VERSION 5.8 ;
BUSBITCHARS "[]" ;
DIVIDERCHAR "/" ;
UNITS
    DATABASE MICRONS 1000 ;
END UNITS

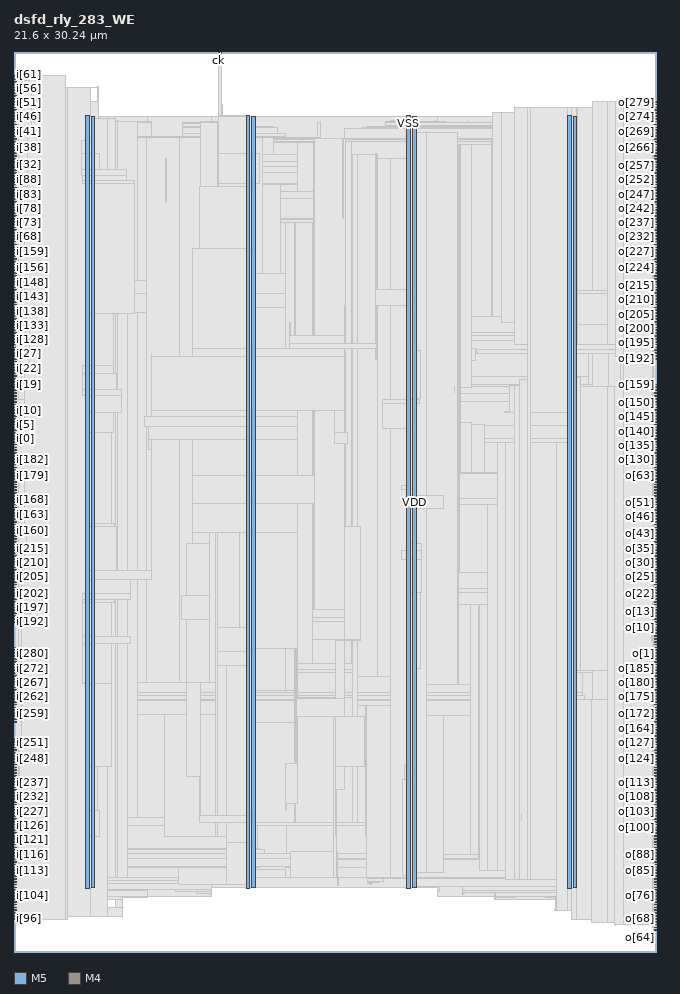
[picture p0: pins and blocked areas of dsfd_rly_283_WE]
MACRO dsfd_rly_283_WE
  FOREIGN dsfd_rly_283_WE 0 0 ;
  CLASS BLOCK ;
  SIZE 21.6 BY 30.24 ;
  PIN ck
    DIRECTION INPUT ;
    USE SIGNAL ;
    PORT
      LAYER M5 ;
        RECT  6.864 30.156 6.888 30.24 ;
    END
  END ck
  PIN i[0]
    DIRECTION INPUT ;
    USE SIGNAL ;
    PORT
      LAYER M4 ;
        RECT  0 17.232 0.084 17.256 ;
    END
  END i[0]
  PIN i[100]
    DIRECTION INPUT ;
    USE SIGNAL ;
    PORT
      LAYER M4 ;
        RECT  0 1.488 0.084 1.512 ;
    END
  END i[100]
  PIN i[101]
    DIRECTION INPUT ;
    USE SIGNAL ;
    PORT
      LAYER M4 ;
        RECT  0 1.584 0.084 1.608 ;
    END
  END i[101]
  PIN i[102]
    DIRECTION INPUT ;
    USE SIGNAL ;
    PORT
      LAYER M4 ;
        RECT  0 1.68 0.084 1.704 ;
    END
  END i[102]
  PIN i[103]
    DIRECTION INPUT ;
    USE SIGNAL ;
    PORT
      LAYER M4 ;
        RECT  0 1.776 0.084 1.8 ;
    END
  END i[103]
  PIN i[104]
    DIRECTION INPUT ;
    USE SIGNAL ;
    PORT
      LAYER M4 ;
        RECT  0 1.872 0.084 1.896 ;
    END
  END i[104]
  PIN i[105]
    DIRECTION INPUT ;
    USE SIGNAL ;
    PORT
      LAYER M4 ;
        RECT  0 1.968 0.084 1.992 ;
    END
  END i[105]
  PIN i[106]
    DIRECTION INPUT ;
    USE SIGNAL ;
    PORT
      LAYER M4 ;
        RECT  0 2.064 0.084 2.088 ;
    END
  END i[106]
  PIN i[107]
    DIRECTION INPUT ;
    USE SIGNAL ;
    PORT
      LAYER M4 ;
        RECT  0 2.16 0.084 2.184 ;
    END
  END i[107]
  PIN i[108]
    DIRECTION INPUT ;
    USE SIGNAL ;
    PORT
      LAYER M4 ;
        RECT  0 2.256 0.084 2.28 ;
    END
  END i[108]
  PIN i[109]
    DIRECTION INPUT ;
    USE SIGNAL ;
    PORT
      LAYER M4 ;
        RECT  0 2.352 0.084 2.376 ;
    END
  END i[109]
  PIN i[10]
    DIRECTION INPUT ;
    USE SIGNAL ;
    PORT
      LAYER M4 ;
        RECT  0 18.192 0.084 18.216 ;
    END
  END i[10]
  PIN i[110]
    DIRECTION INPUT ;
    USE SIGNAL ;
    PORT
      LAYER M4 ;
        RECT  0 2.448 0.084 2.472 ;
    END
  END i[110]
  PIN i[111]
    DIRECTION INPUT ;
    USE SIGNAL ;
    PORT
      LAYER M4 ;
        RECT  0 2.544 0.084 2.568 ;
    END
  END i[111]
  PIN i[112]
    DIRECTION INPUT ;
    USE SIGNAL ;
    PORT
      LAYER M4 ;
        RECT  0 2.64 0.084 2.664 ;
    END
  END i[112]
  PIN i[113]
    DIRECTION INPUT ;
    USE SIGNAL ;
    PORT
      LAYER M4 ;
        RECT  0 2.736 0.084 2.76 ;
    END
  END i[113]
  PIN i[114]
    DIRECTION INPUT ;
    USE SIGNAL ;
    PORT
      LAYER M4 ;
        RECT  0 2.832 0.084 2.856 ;
    END
  END i[114]
  PIN i[115]
    DIRECTION INPUT ;
    USE SIGNAL ;
    PORT
      LAYER M4 ;
        RECT  0 2.928 0.084 2.952 ;
    END
  END i[115]
  PIN i[116]
    DIRECTION INPUT ;
    USE SIGNAL ;
    PORT
      LAYER M4 ;
        RECT  0 3.024 0.084 3.048 ;
    END
  END i[116]
  PIN i[117]
    DIRECTION INPUT ;
    USE SIGNAL ;
    PORT
      LAYER M4 ;
        RECT  0 3.12 0.084 3.144 ;
    END
  END i[117]
  PIN i[118]
    DIRECTION INPUT ;
    USE SIGNAL ;
    PORT
      LAYER M4 ;
        RECT  0 3.216 0.084 3.24 ;
    END
  END i[118]
  PIN i[119]
    DIRECTION INPUT ;
    USE SIGNAL ;
    PORT
      LAYER M4 ;
        RECT  0 3.312 0.084 3.336 ;
    END
  END i[119]
  PIN i[11]
    DIRECTION INPUT ;
    USE SIGNAL ;
    PORT
      LAYER M4 ;
        RECT  0 18.288 0.084 18.312 ;
    END
  END i[11]
  PIN i[120]
    DIRECTION INPUT ;
    USE SIGNAL ;
    PORT
      LAYER M4 ;
        RECT  0 3.408 0.084 3.432 ;
    END
  END i[120]
  PIN i[121]
    DIRECTION INPUT ;
    USE SIGNAL ;
    PORT
      LAYER M4 ;
        RECT  0 3.504 0.084 3.528 ;
    END
  END i[121]
  PIN i[122]
    DIRECTION INPUT ;
    USE SIGNAL ;
    PORT
      LAYER M4 ;
        RECT  0 3.6 0.084 3.624 ;
    END
  END i[122]
  PIN i[123]
    DIRECTION INPUT ;
    USE SIGNAL ;
    PORT
      LAYER M4 ;
        RECT  0 3.696 0.084 3.72 ;
    END
  END i[123]
  PIN i[124]
    DIRECTION INPUT ;
    USE SIGNAL ;
    PORT
      LAYER M4 ;
        RECT  0 3.792 0.084 3.816 ;
    END
  END i[124]
  PIN i[125]
    DIRECTION INPUT ;
    USE SIGNAL ;
    PORT
      LAYER M4 ;
        RECT  0 3.888 0.084 3.912 ;
    END
  END i[125]
  PIN i[126]
    DIRECTION INPUT ;
    USE SIGNAL ;
    PORT
      LAYER M4 ;
        RECT  0 3.984 0.084 4.008 ;
    END
  END i[126]
  PIN i[127]
    DIRECTION INPUT ;
    USE SIGNAL ;
    PORT
      LAYER M4 ;
        RECT  0 4.08 0.084 4.104 ;
    END
  END i[127]
  PIN i[128]
    DIRECTION INPUT ;
    USE SIGNAL ;
    PORT
      LAYER M4 ;
        RECT  0 20.304 0.084 20.328 ;
    END
  END i[128]
  PIN i[129]
    DIRECTION INPUT ;
    USE SIGNAL ;
    PORT
      LAYER M4 ;
        RECT  0 20.4 0.084 20.424 ;
    END
  END i[129]
  PIN i[12]
    DIRECTION INPUT ;
    USE SIGNAL ;
    PORT
      LAYER M4 ;
        RECT  0 18.384 0.084 18.408 ;
    END
  END i[12]
  PIN i[130]
    DIRECTION INPUT ;
    USE SIGNAL ;
    PORT
      LAYER M4 ;
        RECT  0 20.496 0.084 20.52 ;
    END
  END i[130]
  PIN i[131]
    DIRECTION INPUT ;
    USE SIGNAL ;
    PORT
      LAYER M4 ;
        RECT  0 20.592 0.084 20.616 ;
    END
  END i[131]
  PIN i[132]
    DIRECTION INPUT ;
    USE SIGNAL ;
    PORT
      LAYER M4 ;
        RECT  0 20.688 0.084 20.712 ;
    END
  END i[132]
  PIN i[133]
    DIRECTION INPUT ;
    USE SIGNAL ;
    PORT
      LAYER M4 ;
        RECT  0 20.784 0.084 20.808 ;
    END
  END i[133]
  PIN i[134]
    DIRECTION INPUT ;
    USE SIGNAL ;
    PORT
      LAYER M4 ;
        RECT  0 20.88 0.084 20.904 ;
    END
  END i[134]
  PIN i[135]
    DIRECTION INPUT ;
    USE SIGNAL ;
    PORT
      LAYER M4 ;
        RECT  0 20.976 0.084 21 ;
    END
  END i[135]
  PIN i[136]
    DIRECTION INPUT ;
    USE SIGNAL ;
    PORT
      LAYER M4 ;
        RECT  0 21.072 0.084 21.096 ;
    END
  END i[136]
  PIN i[137]
    DIRECTION INPUT ;
    USE SIGNAL ;
    PORT
      LAYER M4 ;
        RECT  0 21.168 0.084 21.192 ;
    END
  END i[137]
  PIN i[138]
    DIRECTION INPUT ;
    USE SIGNAL ;
    PORT
      LAYER M4 ;
        RECT  0 21.264 0.084 21.288 ;
    END
  END i[138]
  PIN i[139]
    DIRECTION INPUT ;
    USE SIGNAL ;
    PORT
      LAYER M4 ;
        RECT  0 21.36 0.084 21.384 ;
    END
  END i[139]
  PIN i[13]
    DIRECTION INPUT ;
    USE SIGNAL ;
    PORT
      LAYER M4 ;
        RECT  0 18.48 0.084 18.504 ;
    END
  END i[13]
  PIN i[140]
    DIRECTION INPUT ;
    USE SIGNAL ;
    PORT
      LAYER M4 ;
        RECT  0 21.456 0.084 21.48 ;
    END
  END i[140]
  PIN i[141]
    DIRECTION INPUT ;
    USE SIGNAL ;
    PORT
      LAYER M4 ;
        RECT  0 21.552 0.084 21.576 ;
    END
  END i[141]
  PIN i[142]
    DIRECTION INPUT ;
    USE SIGNAL ;
    PORT
      LAYER M4 ;
        RECT  0 21.648 0.084 21.672 ;
    END
  END i[142]
  PIN i[143]
    DIRECTION INPUT ;
    USE SIGNAL ;
    PORT
      LAYER M4 ;
        RECT  0 21.744 0.084 21.768 ;
    END
  END i[143]
  PIN i[144]
    DIRECTION INPUT ;
    USE SIGNAL ;
    PORT
      LAYER M4 ;
        RECT  0 21.84 0.084 21.864 ;
    END
  END i[144]
  PIN i[145]
    DIRECTION INPUT ;
    USE SIGNAL ;
    PORT
      LAYER M4 ;
        RECT  0 21.936 0.084 21.96 ;
    END
  END i[145]
  PIN i[146]
    DIRECTION INPUT ;
    USE SIGNAL ;
    PORT
      LAYER M4 ;
        RECT  0 22.032 0.084 22.056 ;
    END
  END i[146]
  PIN i[147]
    DIRECTION INPUT ;
    USE SIGNAL ;
    PORT
      LAYER M4 ;
        RECT  0 22.128 0.084 22.152 ;
    END
  END i[147]
  PIN i[148]
    DIRECTION INPUT ;
    USE SIGNAL ;
    PORT
      LAYER M4 ;
        RECT  0 22.224 0.084 22.248 ;
    END
  END i[148]
  PIN i[149]
    DIRECTION INPUT ;
    USE SIGNAL ;
    PORT
      LAYER M4 ;
        RECT  0 22.32 0.084 22.344 ;
    END
  END i[149]
  PIN i[14]
    DIRECTION INPUT ;
    USE SIGNAL ;
    PORT
      LAYER M4 ;
        RECT  0 18.576 0.084 18.6 ;
    END
  END i[14]
  PIN i[150]
    DIRECTION INPUT ;
    USE SIGNAL ;
    PORT
      LAYER M4 ;
        RECT  0 22.416 0.084 22.44 ;
    END
  END i[150]
  PIN i[151]
    DIRECTION INPUT ;
    USE SIGNAL ;
    PORT
      LAYER M4 ;
        RECT  0 22.512 0.084 22.536 ;
    END
  END i[151]
  PIN i[152]
    DIRECTION INPUT ;
    USE SIGNAL ;
    PORT
      LAYER M4 ;
        RECT  0 22.608 0.084 22.632 ;
    END
  END i[152]
  PIN i[153]
    DIRECTION INPUT ;
    USE SIGNAL ;
    PORT
      LAYER M4 ;
        RECT  0 22.704 0.084 22.728 ;
    END
  END i[153]
  PIN i[154]
    DIRECTION INPUT ;
    USE SIGNAL ;
    PORT
      LAYER M4 ;
        RECT  0 22.8 0.084 22.824 ;
    END
  END i[154]
  PIN i[155]
    DIRECTION INPUT ;
    USE SIGNAL ;
    PORT
      LAYER M4 ;
        RECT  0 22.896 0.084 22.92 ;
    END
  END i[155]
  PIN i[156]
    DIRECTION INPUT ;
    USE SIGNAL ;
    PORT
      LAYER M4 ;
        RECT  0 22.992 0.084 23.016 ;
    END
  END i[156]
  PIN i[157]
    DIRECTION INPUT ;
    USE SIGNAL ;
    PORT
      LAYER M4 ;
        RECT  0 23.088 0.084 23.112 ;
    END
  END i[157]
  PIN i[158]
    DIRECTION INPUT ;
    USE SIGNAL ;
    PORT
      LAYER M4 ;
        RECT  0 23.184 0.084 23.208 ;
    END
  END i[158]
  PIN i[159]
    DIRECTION INPUT ;
    USE SIGNAL ;
    PORT
      LAYER M4 ;
        RECT  0 23.28 0.084 23.304 ;
    END
  END i[159]
  PIN i[15]
    DIRECTION INPUT ;
    USE SIGNAL ;
    PORT
      LAYER M4 ;
        RECT  0 18.672 0.084 18.696 ;
    END
  END i[15]
  PIN i[160]
    DIRECTION INPUT ;
    USE SIGNAL ;
    PORT
      LAYER M4 ;
        RECT  0 14.16 0.084 14.184 ;
    END
  END i[160]
  PIN i[161]
    DIRECTION INPUT ;
    USE SIGNAL ;
    PORT
      LAYER M4 ;
        RECT  0 14.256 0.084 14.28 ;
    END
  END i[161]
  PIN i[162]
    DIRECTION INPUT ;
    USE SIGNAL ;
    PORT
      LAYER M4 ;
        RECT  0 14.352 0.084 14.376 ;
    END
  END i[162]
  PIN i[163]
    DIRECTION INPUT ;
    USE SIGNAL ;
    PORT
      LAYER M4 ;
        RECT  0 14.448 0.084 14.472 ;
    END
  END i[163]
  PIN i[164]
    DIRECTION INPUT ;
    USE SIGNAL ;
    PORT
      LAYER M4 ;
        RECT  0 14.544 0.084 14.568 ;
    END
  END i[164]
  PIN i[165]
    DIRECTION INPUT ;
    USE SIGNAL ;
    PORT
      LAYER M4 ;
        RECT  0 14.64 0.084 14.664 ;
    END
  END i[165]
  PIN i[166]
    DIRECTION INPUT ;
    USE SIGNAL ;
    PORT
      LAYER M4 ;
        RECT  0 14.736 0.084 14.76 ;
    END
  END i[166]
  PIN i[167]
    DIRECTION INPUT ;
    USE SIGNAL ;
    PORT
      LAYER M4 ;
        RECT  0 14.832 0.084 14.856 ;
    END
  END i[167]
  PIN i[168]
    DIRECTION INPUT ;
    USE SIGNAL ;
    PORT
      LAYER M4 ;
        RECT  0 14.928 0.084 14.952 ;
    END
  END i[168]
  PIN i[169]
    DIRECTION INPUT ;
    USE SIGNAL ;
    PORT
      LAYER M4 ;
        RECT  0 15.024 0.084 15.048 ;
    END
  END i[169]
  PIN i[16]
    DIRECTION INPUT ;
    USE SIGNAL ;
    PORT
      LAYER M4 ;
        RECT  0 18.768 0.084 18.792 ;
    END
  END i[16]
  PIN i[170]
    DIRECTION INPUT ;
    USE SIGNAL ;
    PORT
      LAYER M4 ;
        RECT  0 15.12 0.084 15.144 ;
    END
  END i[170]
  PIN i[171]
    DIRECTION INPUT ;
    USE SIGNAL ;
    PORT
      LAYER M4 ;
        RECT  0 15.216 0.084 15.24 ;
    END
  END i[171]
  PIN i[172]
    DIRECTION INPUT ;
    USE SIGNAL ;
    PORT
      LAYER M4 ;
        RECT  0 15.312 0.084 15.336 ;
    END
  END i[172]
  PIN i[173]
    DIRECTION INPUT ;
    USE SIGNAL ;
    PORT
      LAYER M4 ;
        RECT  0 15.408 0.084 15.432 ;
    END
  END i[173]
  PIN i[174]
    DIRECTION INPUT ;
    USE SIGNAL ;
    PORT
      LAYER M4 ;
        RECT  0 15.504 0.084 15.528 ;
    END
  END i[174]
  PIN i[175]
    DIRECTION INPUT ;
    USE SIGNAL ;
    PORT
      LAYER M4 ;
        RECT  0 15.6 0.084 15.624 ;
    END
  END i[175]
  PIN i[176]
    DIRECTION INPUT ;
    USE SIGNAL ;
    PORT
      LAYER M4 ;
        RECT  0 15.696 0.084 15.72 ;
    END
  END i[176]
  PIN i[177]
    DIRECTION INPUT ;
    USE SIGNAL ;
    PORT
      LAYER M4 ;
        RECT  0 15.792 0.084 15.816 ;
    END
  END i[177]
  PIN i[178]
    DIRECTION INPUT ;
    USE SIGNAL ;
    PORT
      LAYER M4 ;
        RECT  0 15.888 0.084 15.912 ;
    END
  END i[178]
  PIN i[179]
    DIRECTION INPUT ;
    USE SIGNAL ;
    PORT
      LAYER M4 ;
        RECT  0 15.984 0.084 16.008 ;
    END
  END i[179]
  PIN i[17]
    DIRECTION INPUT ;
    USE SIGNAL ;
    PORT
      LAYER M4 ;
        RECT  0 18.864 0.084 18.888 ;
    END
  END i[17]
  PIN i[180]
    DIRECTION INPUT ;
    USE SIGNAL ;
    PORT
      LAYER M4 ;
        RECT  0 16.08 0.084 16.104 ;
    END
  END i[180]
  PIN i[181]
    DIRECTION INPUT ;
    USE SIGNAL ;
    PORT
      LAYER M4 ;
        RECT  0 16.176 0.084 16.2 ;
    END
  END i[181]
  PIN i[182]
    DIRECTION INPUT ;
    USE SIGNAL ;
    PORT
      LAYER M4 ;
        RECT  0 16.272 0.084 16.296 ;
    END
  END i[182]
  PIN i[183]
    DIRECTION INPUT ;
    USE SIGNAL ;
    PORT
      LAYER M4 ;
        RECT  0 16.368 0.084 16.392 ;
    END
  END i[183]
  PIN i[184]
    DIRECTION INPUT ;
    USE SIGNAL ;
    PORT
      LAYER M4 ;
        RECT  0 16.464 0.084 16.488 ;
    END
  END i[184]
  PIN i[185]
    DIRECTION INPUT ;
    USE SIGNAL ;
    PORT
      LAYER M4 ;
        RECT  0 16.56 0.084 16.584 ;
    END
  END i[185]
  PIN i[186]
    DIRECTION INPUT ;
    USE SIGNAL ;
    PORT
      LAYER M4 ;
        RECT  0 16.656 0.084 16.68 ;
    END
  END i[186]
  PIN i[187]
    DIRECTION INPUT ;
    USE SIGNAL ;
    PORT
      LAYER M4 ;
        RECT  0 16.752 0.084 16.776 ;
    END
  END i[187]
  PIN i[188]
    DIRECTION INPUT ;
    USE SIGNAL ;
    PORT
      LAYER M4 ;
        RECT  0 16.848 0.084 16.872 ;
    END
  END i[188]
  PIN i[189]
    DIRECTION INPUT ;
    USE SIGNAL ;
    PORT
      LAYER M4 ;
        RECT  0 16.944 0.084 16.968 ;
    END
  END i[189]
  PIN i[18]
    DIRECTION INPUT ;
    USE SIGNAL ;
    PORT
      LAYER M4 ;
        RECT  0 18.96 0.084 18.984 ;
    END
  END i[18]
  PIN i[190]
    DIRECTION INPUT ;
    USE SIGNAL ;
    PORT
      LAYER M4 ;
        RECT  0 17.04 0.084 17.064 ;
    END
  END i[190]
  PIN i[191]
    DIRECTION INPUT ;
    USE SIGNAL ;
    PORT
      LAYER M4 ;
        RECT  0 17.136 0.084 17.16 ;
    END
  END i[191]
  PIN i[192]
    DIRECTION INPUT ;
    USE SIGNAL ;
    PORT
      LAYER M4 ;
        RECT  0 11.088 0.084 11.112 ;
    END
  END i[192]
  PIN i[193]
    DIRECTION INPUT ;
    USE SIGNAL ;
    PORT
      LAYER M4 ;
        RECT  0 11.184 0.084 11.208 ;
    END
  END i[193]
  PIN i[194]
    DIRECTION INPUT ;
    USE SIGNAL ;
    PORT
      LAYER M4 ;
        RECT  0 11.28 0.084 11.304 ;
    END
  END i[194]
  PIN i[195]
    DIRECTION INPUT ;
    USE SIGNAL ;
    PORT
      LAYER M4 ;
        RECT  0 11.376 0.084 11.4 ;
    END
  END i[195]
  PIN i[196]
    DIRECTION INPUT ;
    USE SIGNAL ;
    PORT
      LAYER M4 ;
        RECT  0 11.472 0.084 11.496 ;
    END
  END i[196]
  PIN i[197]
    DIRECTION INPUT ;
    USE SIGNAL ;
    PORT
      LAYER M4 ;
        RECT  0 11.568 0.084 11.592 ;
    END
  END i[197]
  PIN i[198]
    DIRECTION INPUT ;
    USE SIGNAL ;
    PORT
      LAYER M4 ;
        RECT  0 11.664 0.084 11.688 ;
    END
  END i[198]
  PIN i[199]
    DIRECTION INPUT ;
    USE SIGNAL ;
    PORT
      LAYER M4 ;
        RECT  0 11.76 0.084 11.784 ;
    END
  END i[199]
  PIN i[19]
    DIRECTION INPUT ;
    USE SIGNAL ;
    PORT
      LAYER M4 ;
        RECT  0 19.056 0.084 19.08 ;
    END
  END i[19]
  PIN i[1]
    DIRECTION INPUT ;
    USE SIGNAL ;
    PORT
      LAYER M4 ;
        RECT  0 17.328 0.084 17.352 ;
    END
  END i[1]
  PIN i[200]
    DIRECTION INPUT ;
    USE SIGNAL ;
    PORT
      LAYER M4 ;
        RECT  0 11.856 0.084 11.88 ;
    END
  END i[200]
  PIN i[201]
    DIRECTION INPUT ;
    USE SIGNAL ;
    PORT
      LAYER M4 ;
        RECT  0 11.952 0.084 11.976 ;
    END
  END i[201]
  PIN i[202]
    DIRECTION INPUT ;
    USE SIGNAL ;
    PORT
      LAYER M4 ;
        RECT  0 12.048 0.084 12.072 ;
    END
  END i[202]
  PIN i[203]
    DIRECTION INPUT ;
    USE SIGNAL ;
    PORT
      LAYER M4 ;
        RECT  0 12.144 0.084 12.168 ;
    END
  END i[203]
  PIN i[204]
    DIRECTION INPUT ;
    USE SIGNAL ;
    PORT
      LAYER M4 ;
        RECT  0 12.24 0.084 12.264 ;
    END
  END i[204]
  PIN i[205]
    DIRECTION INPUT ;
    USE SIGNAL ;
    PORT
      LAYER M4 ;
        RECT  0 12.336 0.084 12.36 ;
    END
  END i[205]
  PIN i[206]
    DIRECTION INPUT ;
    USE SIGNAL ;
    PORT
      LAYER M4 ;
        RECT  0 12.432 0.084 12.456 ;
    END
  END i[206]
  PIN i[207]
    DIRECTION INPUT ;
    USE SIGNAL ;
    PORT
      LAYER M4 ;
        RECT  0 12.528 0.084 12.552 ;
    END
  END i[207]
  PIN i[208]
    DIRECTION INPUT ;
    USE SIGNAL ;
    PORT
      LAYER M4 ;
        RECT  0 12.624 0.084 12.648 ;
    END
  END i[208]
  PIN i[209]
    DIRECTION INPUT ;
    USE SIGNAL ;
    PORT
      LAYER M4 ;
        RECT  0 12.72 0.084 12.744 ;
    END
  END i[209]
  PIN i[20]
    DIRECTION INPUT ;
    USE SIGNAL ;
    PORT
      LAYER M4 ;
        RECT  0 19.152 0.084 19.176 ;
    END
  END i[20]
  PIN i[210]
    DIRECTION INPUT ;
    USE SIGNAL ;
    PORT
      LAYER M4 ;
        RECT  0 12.816 0.084 12.84 ;
    END
  END i[210]
  PIN i[211]
    DIRECTION INPUT ;
    USE SIGNAL ;
    PORT
      LAYER M4 ;
        RECT  0 12.912 0.084 12.936 ;
    END
  END i[211]
  PIN i[212]
    DIRECTION INPUT ;
    USE SIGNAL ;
    PORT
      LAYER M4 ;
        RECT  0 13.008 0.084 13.032 ;
    END
  END i[212]
  PIN i[213]
    DIRECTION INPUT ;
    USE SIGNAL ;
    PORT
      LAYER M4 ;
        RECT  0 13.104 0.084 13.128 ;
    END
  END i[213]
  PIN i[214]
    DIRECTION INPUT ;
    USE SIGNAL ;
    PORT
      LAYER M4 ;
        RECT  0 13.2 0.084 13.224 ;
    END
  END i[214]
  PIN i[215]
    DIRECTION INPUT ;
    USE SIGNAL ;
    PORT
      LAYER M4 ;
        RECT  0 13.296 0.084 13.32 ;
    END
  END i[215]
  PIN i[216]
    DIRECTION INPUT ;
    USE SIGNAL ;
    PORT
      LAYER M4 ;
        RECT  0 13.392 0.084 13.416 ;
    END
  END i[216]
  PIN i[217]
    DIRECTION INPUT ;
    USE SIGNAL ;
    PORT
      LAYER M4 ;
        RECT  0 13.488 0.084 13.512 ;
    END
  END i[217]
  PIN i[218]
    DIRECTION INPUT ;
    USE SIGNAL ;
    PORT
      LAYER M4 ;
        RECT  0 13.584 0.084 13.608 ;
    END
  END i[218]
  PIN i[219]
    DIRECTION INPUT ;
    USE SIGNAL ;
    PORT
      LAYER M4 ;
        RECT  0 13.68 0.084 13.704 ;
    END
  END i[219]
  PIN i[21]
    DIRECTION INPUT ;
    USE SIGNAL ;
    PORT
      LAYER M4 ;
        RECT  0 19.248 0.084 19.272 ;
    END
  END i[21]
  PIN i[220]
    DIRECTION INPUT ;
    USE SIGNAL ;
    PORT
      LAYER M4 ;
        RECT  0 13.776 0.084 13.8 ;
    END
  END i[220]
  PIN i[221]
    DIRECTION INPUT ;
    USE SIGNAL ;
    PORT
      LAYER M4 ;
        RECT  0 13.872 0.084 13.896 ;
    END
  END i[221]
  PIN i[222]
    DIRECTION INPUT ;
    USE SIGNAL ;
    PORT
      LAYER M4 ;
        RECT  0 13.968 0.084 13.992 ;
    END
  END i[222]
  PIN i[223]
    DIRECTION INPUT ;
    USE SIGNAL ;
    PORT
      LAYER M4 ;
        RECT  0 14.064 0.084 14.088 ;
    END
  END i[223]
  PIN i[224]
    DIRECTION INPUT ;
    USE SIGNAL ;
    PORT
      LAYER M4 ;
        RECT  0 4.176 0.084 4.2 ;
    END
  END i[224]
  PIN i[225]
    DIRECTION INPUT ;
    USE SIGNAL ;
    PORT
      LAYER M4 ;
        RECT  0 4.272 0.084 4.296 ;
    END
  END i[225]
  PIN i[226]
    DIRECTION INPUT ;
    USE SIGNAL ;
    PORT
      LAYER M4 ;
        RECT  0 4.368 0.084 4.392 ;
    END
  END i[226]
  PIN i[227]
    DIRECTION INPUT ;
    USE SIGNAL ;
    PORT
      LAYER M4 ;
        RECT  0 4.464 0.084 4.488 ;
    END
  END i[227]
  PIN i[228]
    DIRECTION INPUT ;
    USE SIGNAL ;
    PORT
      LAYER M4 ;
        RECT  0 4.56 0.084 4.584 ;
    END
  END i[228]
  PIN i[229]
    DIRECTION INPUT ;
    USE SIGNAL ;
    PORT
      LAYER M4 ;
        RECT  0 4.656 0.084 4.68 ;
    END
  END i[229]
  PIN i[22]
    DIRECTION INPUT ;
    USE SIGNAL ;
    PORT
      LAYER M4 ;
        RECT  0 19.344 0.084 19.368 ;
    END
  END i[22]
  PIN i[230]
    DIRECTION INPUT ;
    USE SIGNAL ;
    PORT
      LAYER M4 ;
        RECT  0 4.752 0.084 4.776 ;
    END
  END i[230]
  PIN i[231]
    DIRECTION INPUT ;
    USE SIGNAL ;
    PORT
      LAYER M4 ;
        RECT  0 4.848 0.084 4.872 ;
    END
  END i[231]
  PIN i[232]
    DIRECTION INPUT ;
    USE SIGNAL ;
    PORT
      LAYER M4 ;
        RECT  0 4.944 0.084 4.968 ;
    END
  END i[232]
  PIN i[233]
    DIRECTION INPUT ;
    USE SIGNAL ;
    PORT
      LAYER M4 ;
        RECT  0 5.04 0.084 5.064 ;
    END
  END i[233]
  PIN i[234]
    DIRECTION INPUT ;
    USE SIGNAL ;
    PORT
      LAYER M4 ;
        RECT  0 5.136 0.084 5.16 ;
    END
  END i[234]
  PIN i[235]
    DIRECTION INPUT ;
    USE SIGNAL ;
    PORT
      LAYER M4 ;
        RECT  0 5.232 0.084 5.256 ;
    END
  END i[235]
  PIN i[236]
    DIRECTION INPUT ;
    USE SIGNAL ;
    PORT
      LAYER M4 ;
        RECT  0 5.328 0.084 5.352 ;
    END
  END i[236]
  PIN i[237]
    DIRECTION INPUT ;
    USE SIGNAL ;
    PORT
      LAYER M4 ;
        RECT  0 5.424 0.084 5.448 ;
    END
  END i[237]
  PIN i[238]
    DIRECTION INPUT ;
    USE SIGNAL ;
    PORT
      LAYER M4 ;
        RECT  0 5.52 0.084 5.544 ;
    END
  END i[238]
  PIN i[239]
    DIRECTION INPUT ;
    USE SIGNAL ;
    PORT
      LAYER M4 ;
        RECT  0 5.616 0.084 5.64 ;
    END
  END i[239]
  PIN i[23]
    DIRECTION INPUT ;
    USE SIGNAL ;
    PORT
      LAYER M4 ;
        RECT  0 19.44 0.084 19.464 ;
    END
  END i[23]
  PIN i[240]
    DIRECTION INPUT ;
    USE SIGNAL ;
    PORT
      LAYER M4 ;
        RECT  0 5.712 0.084 5.736 ;
    END
  END i[240]
  PIN i[241]
    DIRECTION INPUT ;
    USE SIGNAL ;
    PORT
      LAYER M4 ;
        RECT  0 5.808 0.084 5.832 ;
    END
  END i[241]
  PIN i[242]
    DIRECTION INPUT ;
    USE SIGNAL ;
    PORT
      LAYER M4 ;
        RECT  0 5.904 0.084 5.928 ;
    END
  END i[242]
  PIN i[243]
    DIRECTION INPUT ;
    USE SIGNAL ;
    PORT
      LAYER M4 ;
        RECT  0 6 0.084 6.024 ;
    END
  END i[243]
  PIN i[244]
    DIRECTION INPUT ;
    USE SIGNAL ;
    PORT
      LAYER M4 ;
        RECT  0 6.096 0.084 6.12 ;
    END
  END i[244]
  PIN i[245]
    DIRECTION INPUT ;
    USE SIGNAL ;
    PORT
      LAYER M4 ;
        RECT  0 6.192 0.084 6.216 ;
    END
  END i[245]
  PIN i[246]
    DIRECTION INPUT ;
    USE SIGNAL ;
    PORT
      LAYER M4 ;
        RECT  0 6.288 0.084 6.312 ;
    END
  END i[246]
  PIN i[247]
    DIRECTION INPUT ;
    USE SIGNAL ;
    PORT
      LAYER M4 ;
        RECT  0 6.384 0.084 6.408 ;
    END
  END i[247]
  PIN i[248]
    DIRECTION INPUT ;
    USE SIGNAL ;
    PORT
      LAYER M4 ;
        RECT  0 6.48 0.084 6.504 ;
    END
  END i[248]
  PIN i[249]
    DIRECTION INPUT ;
    USE SIGNAL ;
    PORT
      LAYER M4 ;
        RECT  0 6.576 0.084 6.6 ;
    END
  END i[249]
  PIN i[24]
    DIRECTION INPUT ;
    USE SIGNAL ;
    PORT
      LAYER M4 ;
        RECT  0 19.536 0.084 19.56 ;
    END
  END i[24]
  PIN i[250]
    DIRECTION INPUT ;
    USE SIGNAL ;
    PORT
      LAYER M4 ;
        RECT  0 6.672 0.084 6.696 ;
    END
  END i[250]
  PIN i[251]
    DIRECTION INPUT ;
    USE SIGNAL ;
    PORT
      LAYER M4 ;
        RECT  0 6.768 0.084 6.792 ;
    END
  END i[251]
  PIN i[252]
    DIRECTION INPUT ;
    USE SIGNAL ;
    PORT
      LAYER M4 ;
        RECT  0 6.864 0.084 6.888 ;
    END
  END i[252]
  PIN i[253]
    DIRECTION INPUT ;
    USE SIGNAL ;
    PORT
      LAYER M4 ;
        RECT  0 6.96 0.084 6.984 ;
    END
  END i[253]
  PIN i[254]
    DIRECTION INPUT ;
    USE SIGNAL ;
    PORT
      LAYER M4 ;
        RECT  0 7.056 0.084 7.08 ;
    END
  END i[254]
  PIN i[255]
    DIRECTION INPUT ;
    USE SIGNAL ;
    PORT
      LAYER M4 ;
        RECT  0 7.152 0.084 7.176 ;
    END
  END i[255]
  PIN i[256]
    DIRECTION INPUT ;
    USE SIGNAL ;
    PORT
      LAYER M4 ;
        RECT  0 7.728 0.084 7.752 ;
    END
  END i[256]
  PIN i[257]
    DIRECTION INPUT ;
    USE SIGNAL ;
    PORT
      LAYER M4 ;
        RECT  0 7.824 0.084 7.848 ;
    END
  END i[257]
  PIN i[258]
    DIRECTION INPUT ;
    USE SIGNAL ;
    PORT
      LAYER M4 ;
        RECT  0 7.92 0.084 7.944 ;
    END
  END i[258]
  PIN i[259]
    DIRECTION INPUT ;
    USE SIGNAL ;
    PORT
      LAYER M4 ;
        RECT  0 8.016 0.084 8.04 ;
    END
  END i[259]
  PIN i[25]
    DIRECTION INPUT ;
    USE SIGNAL ;
    PORT
      LAYER M4 ;
        RECT  0 19.632 0.084 19.656 ;
    END
  END i[25]
  PIN i[260]
    DIRECTION INPUT ;
    USE SIGNAL ;
    PORT
      LAYER M4 ;
        RECT  0 8.112 0.084 8.136 ;
    END
  END i[260]
  PIN i[261]
    DIRECTION INPUT ;
    USE SIGNAL ;
    PORT
      LAYER M4 ;
        RECT  0 8.208 0.084 8.232 ;
    END
  END i[261]
  PIN i[262]
    DIRECTION INPUT ;
    USE SIGNAL ;
    PORT
      LAYER M4 ;
        RECT  0 8.304 0.084 8.328 ;
    END
  END i[262]
  PIN i[263]
    DIRECTION INPUT ;
    USE SIGNAL ;
    PORT
      LAYER M4 ;
        RECT  0 8.4 0.084 8.424 ;
    END
  END i[263]
  PIN i[264]
    DIRECTION INPUT ;
    USE SIGNAL ;
    PORT
      LAYER M4 ;
        RECT  0 8.496 0.084 8.52 ;
    END
  END i[264]
  PIN i[265]
    DIRECTION INPUT ;
    USE SIGNAL ;
    PORT
      LAYER M4 ;
        RECT  0 8.592 0.084 8.616 ;
    END
  END i[265]
  PIN i[266]
    DIRECTION INPUT ;
    USE SIGNAL ;
    PORT
      LAYER M4 ;
        RECT  0 8.688 0.084 8.712 ;
    END
  END i[266]
  PIN i[267]
    DIRECTION INPUT ;
    USE SIGNAL ;
    PORT
      LAYER M4 ;
        RECT  0 8.784 0.084 8.808 ;
    END
  END i[267]
  PIN i[268]
    DIRECTION INPUT ;
    USE SIGNAL ;
    PORT
      LAYER M4 ;
        RECT  0 8.88 0.084 8.904 ;
    END
  END i[268]
  PIN i[269]
    DIRECTION INPUT ;
    USE SIGNAL ;
    PORT
      LAYER M4 ;
        RECT  0 8.976 0.084 9 ;
    END
  END i[269]
  PIN i[26]
    DIRECTION INPUT ;
    USE SIGNAL ;
    PORT
      LAYER M4 ;
        RECT  0 19.728 0.084 19.752 ;
    END
  END i[26]
  PIN i[270]
    DIRECTION INPUT ;
    USE SIGNAL ;
    PORT
      LAYER M4 ;
        RECT  0 9.072 0.084 9.096 ;
    END
  END i[270]
  PIN i[271]
    DIRECTION INPUT ;
    USE SIGNAL ;
    PORT
      LAYER M4 ;
        RECT  0 9.168 0.084 9.192 ;
    END
  END i[271]
  PIN i[272]
    DIRECTION INPUT ;
    USE SIGNAL ;
    PORT
      LAYER M4 ;
        RECT  0 9.264 0.084 9.288 ;
    END
  END i[272]
  PIN i[273]
    DIRECTION INPUT ;
    USE SIGNAL ;
    PORT
      LAYER M4 ;
        RECT  0 9.36 0.084 9.384 ;
    END
  END i[273]
  PIN i[274]
    DIRECTION INPUT ;
    USE SIGNAL ;
    PORT
      LAYER M4 ;
        RECT  0 9.456 0.084 9.48 ;
    END
  END i[274]
  PIN i[275]
    DIRECTION INPUT ;
    USE SIGNAL ;
    PORT
      LAYER M4 ;
        RECT  0 9.552 0.084 9.576 ;
    END
  END i[275]
  PIN i[276]
    DIRECTION INPUT ;
    USE SIGNAL ;
    PORT
      LAYER M4 ;
        RECT  0 9.648 0.084 9.672 ;
    END
  END i[276]
  PIN i[277]
    DIRECTION INPUT ;
    USE SIGNAL ;
    PORT
      LAYER M4 ;
        RECT  0 9.744 0.084 9.768 ;
    END
  END i[277]
  PIN i[278]
    DIRECTION INPUT ;
    USE SIGNAL ;
    PORT
      LAYER M4 ;
        RECT  0 9.84 0.084 9.864 ;
    END
  END i[278]
  PIN i[279]
    DIRECTION INPUT ;
    USE SIGNAL ;
    PORT
      LAYER M4 ;
        RECT  0 9.936 0.084 9.96 ;
    END
  END i[279]
  PIN i[27]
    DIRECTION INPUT ;
    USE SIGNAL ;
    PORT
      LAYER M4 ;
        RECT  0 19.824 0.084 19.848 ;
    END
  END i[27]
  PIN i[280]
    DIRECTION INPUT ;
    USE SIGNAL ;
    PORT
      LAYER M4 ;
        RECT  0 10.032 0.084 10.056 ;
    END
  END i[280]
  PIN i[281]
    DIRECTION INPUT ;
    USE SIGNAL ;
    PORT
      LAYER M4 ;
        RECT  0 10.128 0.084 10.152 ;
    END
  END i[281]
  PIN i[282]
    DIRECTION INPUT ;
    USE SIGNAL ;
    PORT
      LAYER M4 ;
        RECT  0 10.224 0.084 10.248 ;
    END
  END i[282]
  PIN i[28]
    DIRECTION INPUT ;
    USE SIGNAL ;
    PORT
      LAYER M4 ;
        RECT  0 19.92 0.084 19.944 ;
    END
  END i[28]
  PIN i[29]
    DIRECTION INPUT ;
    USE SIGNAL ;
    PORT
      LAYER M4 ;
        RECT  0 20.016 0.084 20.04 ;
    END
  END i[29]
  PIN i[2]
    DIRECTION INPUT ;
    USE SIGNAL ;
    PORT
      LAYER M4 ;
        RECT  0 17.424 0.084 17.448 ;
    END
  END i[2]
  PIN i[30]
    DIRECTION INPUT ;
    USE SIGNAL ;
    PORT
      LAYER M4 ;
        RECT  0 20.112 0.084 20.136 ;
    END
  END i[30]
  PIN i[31]
    DIRECTION INPUT ;
    USE SIGNAL ;
    PORT
      LAYER M4 ;
        RECT  0 20.208 0.084 20.232 ;
    END
  END i[31]
  PIN i[32]
    DIRECTION INPUT ;
    USE SIGNAL ;
    PORT
      LAYER M4 ;
        RECT  0 26.448 0.084 26.472 ;
    END
  END i[32]
  PIN i[33]
    DIRECTION INPUT ;
    USE SIGNAL ;
    PORT
      LAYER M4 ;
        RECT  0 26.544 0.084 26.568 ;
    END
  END i[33]
  PIN i[34]
    DIRECTION INPUT ;
    USE SIGNAL ;
    PORT
      LAYER M4 ;
        RECT  0 26.64 0.084 26.664 ;
    END
  END i[34]
  PIN i[35]
    DIRECTION INPUT ;
    USE SIGNAL ;
    PORT
      LAYER M4 ;
        RECT  0 26.736 0.084 26.76 ;
    END
  END i[35]
  PIN i[36]
    DIRECTION INPUT ;
    USE SIGNAL ;
    PORT
      LAYER M4 ;
        RECT  0 26.832 0.084 26.856 ;
    END
  END i[36]
  PIN i[37]
    DIRECTION INPUT ;
    USE SIGNAL ;
    PORT
      LAYER M4 ;
        RECT  0 26.928 0.084 26.952 ;
    END
  END i[37]
  PIN i[38]
    DIRECTION INPUT ;
    USE SIGNAL ;
    PORT
      LAYER M4 ;
        RECT  0 27.024 0.084 27.048 ;
    END
  END i[38]
  PIN i[39]
    DIRECTION INPUT ;
    USE SIGNAL ;
    PORT
      LAYER M4 ;
        RECT  0 27.12 0.084 27.144 ;
    END
  END i[39]
  PIN i[3]
    DIRECTION INPUT ;
    USE SIGNAL ;
    PORT
      LAYER M4 ;
        RECT  0 17.52 0.084 17.544 ;
    END
  END i[3]
  PIN i[40]
    DIRECTION INPUT ;
    USE SIGNAL ;
    PORT
      LAYER M4 ;
        RECT  0 27.216 0.084 27.24 ;
    END
  END i[40]
  PIN i[41]
    DIRECTION INPUT ;
    USE SIGNAL ;
    PORT
      LAYER M4 ;
        RECT  0 27.312 0.084 27.336 ;
    END
  END i[41]
  PIN i[42]
    DIRECTION INPUT ;
    USE SIGNAL ;
    PORT
      LAYER M4 ;
        RECT  0 27.408 0.084 27.432 ;
    END
  END i[42]
  PIN i[43]
    DIRECTION INPUT ;
    USE SIGNAL ;
    PORT
      LAYER M4 ;
        RECT  0 27.504 0.084 27.528 ;
    END
  END i[43]
  PIN i[44]
    DIRECTION INPUT ;
    USE SIGNAL ;
    PORT
      LAYER M4 ;
        RECT  0 27.6 0.084 27.624 ;
    END
  END i[44]
  PIN i[45]
    DIRECTION INPUT ;
    USE SIGNAL ;
    PORT
      LAYER M4 ;
        RECT  0 27.696 0.084 27.72 ;
    END
  END i[45]
  PIN i[46]
    DIRECTION INPUT ;
    USE SIGNAL ;
    PORT
      LAYER M4 ;
        RECT  0 27.792 0.084 27.816 ;
    END
  END i[46]
  PIN i[47]
    DIRECTION INPUT ;
    USE SIGNAL ;
    PORT
      LAYER M4 ;
        RECT  0 27.888 0.084 27.912 ;
    END
  END i[47]
  PIN i[48]
    DIRECTION INPUT ;
    USE SIGNAL ;
    PORT
      LAYER M4 ;
        RECT  0 27.984 0.084 28.008 ;
    END
  END i[48]
  PIN i[49]
    DIRECTION INPUT ;
    USE SIGNAL ;
    PORT
      LAYER M4 ;
        RECT  0 28.08 0.084 28.104 ;
    END
  END i[49]
  PIN i[4]
    DIRECTION INPUT ;
    USE SIGNAL ;
    PORT
      LAYER M4 ;
        RECT  0 17.616 0.084 17.64 ;
    END
  END i[4]
  PIN i[50]
    DIRECTION INPUT ;
    USE SIGNAL ;
    PORT
      LAYER M4 ;
        RECT  0 28.176 0.084 28.2 ;
    END
  END i[50]
  PIN i[51]
    DIRECTION INPUT ;
    USE SIGNAL ;
    PORT
      LAYER M4 ;
        RECT  0 28.272 0.084 28.296 ;
    END
  END i[51]
  PIN i[52]
    DIRECTION INPUT ;
    USE SIGNAL ;
    PORT
      LAYER M4 ;
        RECT  0 28.368 0.084 28.392 ;
    END
  END i[52]
  PIN i[53]
    DIRECTION INPUT ;
    USE SIGNAL ;
    PORT
      LAYER M4 ;
        RECT  0 28.464 0.084 28.488 ;
    END
  END i[53]
  PIN i[54]
    DIRECTION INPUT ;
    USE SIGNAL ;
    PORT
      LAYER M4 ;
        RECT  0 28.56 0.084 28.584 ;
    END
  END i[54]
  PIN i[55]
    DIRECTION INPUT ;
    USE SIGNAL ;
    PORT
      LAYER M4 ;
        RECT  0 28.656 0.084 28.68 ;
    END
  END i[55]
  PIN i[56]
    DIRECTION INPUT ;
    USE SIGNAL ;
    PORT
      LAYER M4 ;
        RECT  0 28.752 0.084 28.776 ;
    END
  END i[56]
  PIN i[57]
    DIRECTION INPUT ;
    USE SIGNAL ;
    PORT
      LAYER M4 ;
        RECT  0 28.848 0.084 28.872 ;
    END
  END i[57]
  PIN i[58]
    DIRECTION INPUT ;
    USE SIGNAL ;
    PORT
      LAYER M4 ;
        RECT  0 28.944 0.084 28.968 ;
    END
  END i[58]
  PIN i[59]
    DIRECTION INPUT ;
    USE SIGNAL ;
    PORT
      LAYER M4 ;
        RECT  0 29.04 0.084 29.064 ;
    END
  END i[59]
  PIN i[5]
    DIRECTION INPUT ;
    USE SIGNAL ;
    PORT
      LAYER M4 ;
        RECT  0 17.712 0.084 17.736 ;
    END
  END i[5]
  PIN i[60]
    DIRECTION INPUT ;
    USE SIGNAL ;
    PORT
      LAYER M4 ;
        RECT  0 29.136 0.084 29.16 ;
    END
  END i[60]
  PIN i[61]
    DIRECTION INPUT ;
    USE SIGNAL ;
    PORT
      LAYER M4 ;
        RECT  0 29.232 0.084 29.256 ;
    END
  END i[61]
  PIN i[62]
    DIRECTION INPUT ;
    USE SIGNAL ;
    PORT
      LAYER M4 ;
        RECT  0 29.328 0.084 29.352 ;
    END
  END i[62]
  PIN i[63]
    DIRECTION INPUT ;
    USE SIGNAL ;
    PORT
      LAYER M4 ;
        RECT  0 29.424 0.084 29.448 ;
    END
  END i[63]
  PIN i[64]
    DIRECTION INPUT ;
    USE SIGNAL ;
    PORT
      LAYER M4 ;
        RECT  0 23.376 0.084 23.4 ;
    END
  END i[64]
  PIN i[65]
    DIRECTION INPUT ;
    USE SIGNAL ;
    PORT
      LAYER M4 ;
        RECT  0 23.472 0.084 23.496 ;
    END
  END i[65]
  PIN i[66]
    DIRECTION INPUT ;
    USE SIGNAL ;
    PORT
      LAYER M4 ;
        RECT  0 23.568 0.084 23.592 ;
    END
  END i[66]
  PIN i[67]
    DIRECTION INPUT ;
    USE SIGNAL ;
    PORT
      LAYER M4 ;
        RECT  0 23.664 0.084 23.688 ;
    END
  END i[67]
  PIN i[68]
    DIRECTION INPUT ;
    USE SIGNAL ;
    PORT
      LAYER M4 ;
        RECT  0 23.76 0.084 23.784 ;
    END
  END i[68]
  PIN i[69]
    DIRECTION INPUT ;
    USE SIGNAL ;
    PORT
      LAYER M4 ;
        RECT  0 23.856 0.084 23.88 ;
    END
  END i[69]
  PIN i[6]
    DIRECTION INPUT ;
    USE SIGNAL ;
    PORT
      LAYER M4 ;
        RECT  0 17.808 0.084 17.832 ;
    END
  END i[6]
  PIN i[70]
    DIRECTION INPUT ;
    USE SIGNAL ;
    PORT
      LAYER M4 ;
        RECT  0 23.952 0.084 23.976 ;
    END
  END i[70]
  PIN i[71]
    DIRECTION INPUT ;
    USE SIGNAL ;
    PORT
      LAYER M4 ;
        RECT  0 24.048 0.084 24.072 ;
    END
  END i[71]
  PIN i[72]
    DIRECTION INPUT ;
    USE SIGNAL ;
    PORT
      LAYER M4 ;
        RECT  0 24.144 0.084 24.168 ;
    END
  END i[72]
  PIN i[73]
    DIRECTION INPUT ;
    USE SIGNAL ;
    PORT
      LAYER M4 ;
        RECT  0 24.24 0.084 24.264 ;
    END
  END i[73]
  PIN i[74]
    DIRECTION INPUT ;
    USE SIGNAL ;
    PORT
      LAYER M4 ;
        RECT  0 24.336 0.084 24.36 ;
    END
  END i[74]
  PIN i[75]
    DIRECTION INPUT ;
    USE SIGNAL ;
    PORT
      LAYER M4 ;
        RECT  0 24.432 0.084 24.456 ;
    END
  END i[75]
  PIN i[76]
    DIRECTION INPUT ;
    USE SIGNAL ;
    PORT
      LAYER M4 ;
        RECT  0 24.528 0.084 24.552 ;
    END
  END i[76]
  PIN i[77]
    DIRECTION INPUT ;
    USE SIGNAL ;
    PORT
      LAYER M4 ;
        RECT  0 24.624 0.084 24.648 ;
    END
  END i[77]
  PIN i[78]
    DIRECTION INPUT ;
    USE SIGNAL ;
    PORT
      LAYER M4 ;
        RECT  0 24.72 0.084 24.744 ;
    END
  END i[78]
  PIN i[79]
    DIRECTION INPUT ;
    USE SIGNAL ;
    PORT
      LAYER M4 ;
        RECT  0 24.816 0.084 24.84 ;
    END
  END i[79]
  PIN i[7]
    DIRECTION INPUT ;
    USE SIGNAL ;
    PORT
      LAYER M4 ;
        RECT  0 17.904 0.084 17.928 ;
    END
  END i[7]
  PIN i[80]
    DIRECTION INPUT ;
    USE SIGNAL ;
    PORT
      LAYER M4 ;
        RECT  0 24.912 0.084 24.936 ;
    END
  END i[80]
  PIN i[81]
    DIRECTION INPUT ;
    USE SIGNAL ;
    PORT
      LAYER M4 ;
        RECT  0 25.008 0.084 25.032 ;
    END
  END i[81]
  PIN i[82]
    DIRECTION INPUT ;
    USE SIGNAL ;
    PORT
      LAYER M4 ;
        RECT  0 25.104 0.084 25.128 ;
    END
  END i[82]
  PIN i[83]
    DIRECTION INPUT ;
    USE SIGNAL ;
    PORT
      LAYER M4 ;
        RECT  0 25.2 0.084 25.224 ;
    END
  END i[83]
  PIN i[84]
    DIRECTION INPUT ;
    USE SIGNAL ;
    PORT
      LAYER M4 ;
        RECT  0 25.296 0.084 25.32 ;
    END
  END i[84]
  PIN i[85]
    DIRECTION INPUT ;
    USE SIGNAL ;
    PORT
      LAYER M4 ;
        RECT  0 25.392 0.084 25.416 ;
    END
  END i[85]
  PIN i[86]
    DIRECTION INPUT ;
    USE SIGNAL ;
    PORT
      LAYER M4 ;
        RECT  0 25.488 0.084 25.512 ;
    END
  END i[86]
  PIN i[87]
    DIRECTION INPUT ;
    USE SIGNAL ;
    PORT
      LAYER M4 ;
        RECT  0 25.584 0.084 25.608 ;
    END
  END i[87]
  PIN i[88]
    DIRECTION INPUT ;
    USE SIGNAL ;
    PORT
      LAYER M4 ;
        RECT  0 25.68 0.084 25.704 ;
    END
  END i[88]
  PIN i[89]
    DIRECTION INPUT ;
    USE SIGNAL ;
    PORT
      LAYER M4 ;
        RECT  0 25.776 0.084 25.8 ;
    END
  END i[89]
  PIN i[8]
    DIRECTION INPUT ;
    USE SIGNAL ;
    PORT
      LAYER M4 ;
        RECT  0 18 0.084 18.024 ;
    END
  END i[8]
  PIN i[90]
    DIRECTION INPUT ;
    USE SIGNAL ;
    PORT
      LAYER M4 ;
        RECT  0 25.872 0.084 25.896 ;
    END
  END i[90]
  PIN i[91]
    DIRECTION INPUT ;
    USE SIGNAL ;
    PORT
      LAYER M4 ;
        RECT  0 25.968 0.084 25.992 ;
    END
  END i[91]
  PIN i[92]
    DIRECTION INPUT ;
    USE SIGNAL ;
    PORT
      LAYER M4 ;
        RECT  0 26.064 0.084 26.088 ;
    END
  END i[92]
  PIN i[93]
    DIRECTION INPUT ;
    USE SIGNAL ;
    PORT
      LAYER M4 ;
        RECT  0 26.16 0.084 26.184 ;
    END
  END i[93]
  PIN i[94]
    DIRECTION INPUT ;
    USE SIGNAL ;
    PORT
      LAYER M4 ;
        RECT  0 26.256 0.084 26.28 ;
    END
  END i[94]
  PIN i[95]
    DIRECTION INPUT ;
    USE SIGNAL ;
    PORT
      LAYER M4 ;
        RECT  0 26.352 0.084 26.376 ;
    END
  END i[95]
  PIN i[96]
    DIRECTION INPUT ;
    USE SIGNAL ;
    PORT
      LAYER M4 ;
        RECT  0 1.104 0.084 1.128 ;
    END
  END i[96]
  PIN i[97]
    DIRECTION INPUT ;
    USE SIGNAL ;
    PORT
      LAYER M4 ;
        RECT  0 1.2 0.084 1.224 ;
    END
  END i[97]
  PIN i[98]
    DIRECTION INPUT ;
    USE SIGNAL ;
    PORT
      LAYER M4 ;
        RECT  0 1.296 0.084 1.32 ;
    END
  END i[98]
  PIN i[99]
    DIRECTION INPUT ;
    USE SIGNAL ;
    PORT
      LAYER M4 ;
        RECT  0 1.392 0.084 1.416 ;
    END
  END i[99]
  PIN i[9]
    DIRECTION INPUT ;
    USE SIGNAL ;
    PORT
      LAYER M4 ;
        RECT  0 18.096 0.084 18.12 ;
    END
  END i[9]
  PIN o[0]
    DIRECTION OUTPUT ;
    USE SIGNAL ;
    PORT
      LAYER M4 ;
        RECT  21.516 9.936 21.6 9.96 ;
    END
  END o[0]
  PIN o[100]
    DIRECTION OUTPUT ;
    USE SIGNAL ;
    PORT
      LAYER M4 ;
        RECT  21.516 4.176 21.6 4.2 ;
    END
  END o[100]
  PIN o[101]
    DIRECTION OUTPUT ;
    USE SIGNAL ;
    PORT
      LAYER M4 ;
        RECT  21.516 4.272 21.6 4.296 ;
    END
  END o[101]
  PIN o[102]
    DIRECTION OUTPUT ;
    USE SIGNAL ;
    PORT
      LAYER M4 ;
        RECT  21.516 4.368 21.6 4.392 ;
    END
  END o[102]
  PIN o[103]
    DIRECTION OUTPUT ;
    USE SIGNAL ;
    PORT
      LAYER M4 ;
        RECT  21.516 4.464 21.6 4.488 ;
    END
  END o[103]
  PIN o[104]
    DIRECTION OUTPUT ;
    USE SIGNAL ;
    PORT
      LAYER M4 ;
        RECT  21.516 4.56 21.6 4.584 ;
    END
  END o[104]
  PIN o[105]
    DIRECTION OUTPUT ;
    USE SIGNAL ;
    PORT
      LAYER M4 ;
        RECT  21.516 4.656 21.6 4.68 ;
    END
  END o[105]
  PIN o[106]
    DIRECTION OUTPUT ;
    USE SIGNAL ;
    PORT
      LAYER M4 ;
        RECT  21.516 4.752 21.6 4.776 ;
    END
  END o[106]
  PIN o[107]
    DIRECTION OUTPUT ;
    USE SIGNAL ;
    PORT
      LAYER M4 ;
        RECT  21.516 4.848 21.6 4.872 ;
    END
  END o[107]
  PIN o[108]
    DIRECTION OUTPUT ;
    USE SIGNAL ;
    PORT
      LAYER M4 ;
        RECT  21.516 4.944 21.6 4.968 ;
    END
  END o[108]
  PIN o[109]
    DIRECTION OUTPUT ;
    USE SIGNAL ;
    PORT
      LAYER M4 ;
        RECT  21.516 5.04 21.6 5.064 ;
    END
  END o[109]
  PIN o[10]
    DIRECTION OUTPUT ;
    USE SIGNAL ;
    PORT
      LAYER M4 ;
        RECT  21.516 10.896 21.6 10.92 ;
    END
  END o[10]
  PIN o[110]
    DIRECTION OUTPUT ;
    USE SIGNAL ;
    PORT
      LAYER M4 ;
        RECT  21.516 5.136 21.6 5.16 ;
    END
  END o[110]
  PIN o[111]
    DIRECTION OUTPUT ;
    USE SIGNAL ;
    PORT
      LAYER M4 ;
        RECT  21.516 5.232 21.6 5.256 ;
    END
  END o[111]
  PIN o[112]
    DIRECTION OUTPUT ;
    USE SIGNAL ;
    PORT
      LAYER M4 ;
        RECT  21.516 5.328 21.6 5.352 ;
    END
  END o[112]
  PIN o[113]
    DIRECTION OUTPUT ;
    USE SIGNAL ;
    PORT
      LAYER M4 ;
        RECT  21.516 5.424 21.6 5.448 ;
    END
  END o[113]
  PIN o[114]
    DIRECTION OUTPUT ;
    USE SIGNAL ;
    PORT
      LAYER M4 ;
        RECT  21.516 5.52 21.6 5.544 ;
    END
  END o[114]
  PIN o[115]
    DIRECTION OUTPUT ;
    USE SIGNAL ;
    PORT
      LAYER M4 ;
        RECT  21.516 5.616 21.6 5.64 ;
    END
  END o[115]
  PIN o[116]
    DIRECTION OUTPUT ;
    USE SIGNAL ;
    PORT
      LAYER M4 ;
        RECT  21.516 5.712 21.6 5.736 ;
    END
  END o[116]
  PIN o[117]
    DIRECTION OUTPUT ;
    USE SIGNAL ;
    PORT
      LAYER M4 ;
        RECT  21.516 5.808 21.6 5.832 ;
    END
  END o[117]
  PIN o[118]
    DIRECTION OUTPUT ;
    USE SIGNAL ;
    PORT
      LAYER M4 ;
        RECT  21.516 5.904 21.6 5.928 ;
    END
  END o[118]
  PIN o[119]
    DIRECTION OUTPUT ;
    USE SIGNAL ;
    PORT
      LAYER M4 ;
        RECT  21.516 6 21.6 6.024 ;
    END
  END o[119]
  PIN o[11]
    DIRECTION OUTPUT ;
    USE SIGNAL ;
    PORT
      LAYER M4 ;
        RECT  21.516 10.992 21.6 11.016 ;
    END
  END o[11]
  PIN o[120]
    DIRECTION OUTPUT ;
    USE SIGNAL ;
    PORT
      LAYER M4 ;
        RECT  21.516 6.096 21.6 6.12 ;
    END
  END o[120]
  PIN o[121]
    DIRECTION OUTPUT ;
    USE SIGNAL ;
    PORT
      LAYER M4 ;
        RECT  21.516 6.192 21.6 6.216 ;
    END
  END o[121]
  PIN o[122]
    DIRECTION OUTPUT ;
    USE SIGNAL ;
    PORT
      LAYER M4 ;
        RECT  21.516 6.288 21.6 6.312 ;
    END
  END o[122]
  PIN o[123]
    DIRECTION OUTPUT ;
    USE SIGNAL ;
    PORT
      LAYER M4 ;
        RECT  21.516 6.384 21.6 6.408 ;
    END
  END o[123]
  PIN o[124]
    DIRECTION OUTPUT ;
    USE SIGNAL ;
    PORT
      LAYER M4 ;
        RECT  21.516 6.48 21.6 6.504 ;
    END
  END o[124]
  PIN o[125]
    DIRECTION OUTPUT ;
    USE SIGNAL ;
    PORT
      LAYER M4 ;
        RECT  21.516 6.576 21.6 6.6 ;
    END
  END o[125]
  PIN o[126]
    DIRECTION OUTPUT ;
    USE SIGNAL ;
    PORT
      LAYER M4 ;
        RECT  21.516 6.672 21.6 6.696 ;
    END
  END o[126]
  PIN o[127]
    DIRECTION OUTPUT ;
    USE SIGNAL ;
    PORT
      LAYER M4 ;
        RECT  21.516 6.768 21.6 6.792 ;
    END
  END o[127]
  PIN o[128]
    DIRECTION OUTPUT ;
    USE SIGNAL ;
    PORT
      LAYER M4 ;
        RECT  21.516 16.08 21.6 16.104 ;
    END
  END o[128]
  PIN o[129]
    DIRECTION OUTPUT ;
    USE SIGNAL ;
    PORT
      LAYER M4 ;
        RECT  21.516 16.176 21.6 16.2 ;
    END
  END o[129]
  PIN o[12]
    DIRECTION OUTPUT ;
    USE SIGNAL ;
    PORT
      LAYER M4 ;
        RECT  21.516 11.088 21.6 11.112 ;
    END
  END o[12]
  PIN o[130]
    DIRECTION OUTPUT ;
    USE SIGNAL ;
    PORT
      LAYER M4 ;
        RECT  21.516 16.272 21.6 16.296 ;
    END
  END o[130]
  PIN o[131]
    DIRECTION OUTPUT ;
    USE SIGNAL ;
    PORT
      LAYER M4 ;
        RECT  21.516 16.368 21.6 16.392 ;
    END
  END o[131]
  PIN o[132]
    DIRECTION OUTPUT ;
    USE SIGNAL ;
    PORT
      LAYER M4 ;
        RECT  21.516 16.464 21.6 16.488 ;
    END
  END o[132]
  PIN o[133]
    DIRECTION OUTPUT ;
    USE SIGNAL ;
    PORT
      LAYER M4 ;
        RECT  21.516 16.56 21.6 16.584 ;
    END
  END o[133]
  PIN o[134]
    DIRECTION OUTPUT ;
    USE SIGNAL ;
    PORT
      LAYER M4 ;
        RECT  21.516 16.656 21.6 16.68 ;
    END
  END o[134]
  PIN o[135]
    DIRECTION OUTPUT ;
    USE SIGNAL ;
    PORT
      LAYER M4 ;
        RECT  21.516 16.752 21.6 16.776 ;
    END
  END o[135]
  PIN o[136]
    DIRECTION OUTPUT ;
    USE SIGNAL ;
    PORT
      LAYER M4 ;
        RECT  21.516 16.848 21.6 16.872 ;
    END
  END o[136]
  PIN o[137]
    DIRECTION OUTPUT ;
    USE SIGNAL ;
    PORT
      LAYER M4 ;
        RECT  21.516 16.944 21.6 16.968 ;
    END
  END o[137]
  PIN o[138]
    DIRECTION OUTPUT ;
    USE SIGNAL ;
    PORT
      LAYER M4 ;
        RECT  21.516 17.04 21.6 17.064 ;
    END
  END o[138]
  PIN o[139]
    DIRECTION OUTPUT ;
    USE SIGNAL ;
    PORT
      LAYER M4 ;
        RECT  21.516 17.136 21.6 17.16 ;
    END
  END o[139]
  PIN o[13]
    DIRECTION OUTPUT ;
    USE SIGNAL ;
    PORT
      LAYER M4 ;
        RECT  21.516 11.184 21.6 11.208 ;
    END
  END o[13]
  PIN o[140]
    DIRECTION OUTPUT ;
    USE SIGNAL ;
    PORT
      LAYER M4 ;
        RECT  21.516 17.232 21.6 17.256 ;
    END
  END o[140]
  PIN o[141]
    DIRECTION OUTPUT ;
    USE SIGNAL ;
    PORT
      LAYER M4 ;
        RECT  21.516 17.328 21.6 17.352 ;
    END
  END o[141]
  PIN o[142]
    DIRECTION OUTPUT ;
    USE SIGNAL ;
    PORT
      LAYER M4 ;
        RECT  21.516 17.424 21.6 17.448 ;
    END
  END o[142]
  PIN o[143]
    DIRECTION OUTPUT ;
    USE SIGNAL ;
    PORT
      LAYER M4 ;
        RECT  21.516 17.52 21.6 17.544 ;
    END
  END o[143]
  PIN o[144]
    DIRECTION OUTPUT ;
    USE SIGNAL ;
    PORT
      LAYER M4 ;
        RECT  21.516 17.616 21.6 17.64 ;
    END
  END o[144]
  PIN o[145]
    DIRECTION OUTPUT ;
    USE SIGNAL ;
    PORT
      LAYER M4 ;
        RECT  21.516 17.712 21.6 17.736 ;
    END
  END o[145]
  PIN o[146]
    DIRECTION OUTPUT ;
    USE SIGNAL ;
    PORT
      LAYER M4 ;
        RECT  21.516 17.808 21.6 17.832 ;
    END
  END o[146]
  PIN o[147]
    DIRECTION OUTPUT ;
    USE SIGNAL ;
    PORT
      LAYER M4 ;
        RECT  21.516 17.904 21.6 17.928 ;
    END
  END o[147]
  PIN o[148]
    DIRECTION OUTPUT ;
    USE SIGNAL ;
    PORT
      LAYER M4 ;
        RECT  21.516 18 21.6 18.024 ;
    END
  END o[148]
  PIN o[149]
    DIRECTION OUTPUT ;
    USE SIGNAL ;
    PORT
      LAYER M4 ;
        RECT  21.516 18.096 21.6 18.12 ;
    END
  END o[149]
  PIN o[14]
    DIRECTION OUTPUT ;
    USE SIGNAL ;
    PORT
      LAYER M4 ;
        RECT  21.516 11.28 21.6 11.304 ;
    END
  END o[14]
  PIN o[150]
    DIRECTION OUTPUT ;
    USE SIGNAL ;
    PORT
      LAYER M4 ;
        RECT  21.516 18.192 21.6 18.216 ;
    END
  END o[150]
  PIN o[151]
    DIRECTION OUTPUT ;
    USE SIGNAL ;
    PORT
      LAYER M4 ;
        RECT  21.516 18.288 21.6 18.312 ;
    END
  END o[151]
  PIN o[152]
    DIRECTION OUTPUT ;
    USE SIGNAL ;
    PORT
      LAYER M4 ;
        RECT  21.516 18.384 21.6 18.408 ;
    END
  END o[152]
  PIN o[153]
    DIRECTION OUTPUT ;
    USE SIGNAL ;
    PORT
      LAYER M4 ;
        RECT  21.516 18.48 21.6 18.504 ;
    END
  END o[153]
  PIN o[154]
    DIRECTION OUTPUT ;
    USE SIGNAL ;
    PORT
      LAYER M4 ;
        RECT  21.516 18.576 21.6 18.6 ;
    END
  END o[154]
  PIN o[155]
    DIRECTION OUTPUT ;
    USE SIGNAL ;
    PORT
      LAYER M4 ;
        RECT  21.516 18.672 21.6 18.696 ;
    END
  END o[155]
  PIN o[156]
    DIRECTION OUTPUT ;
    USE SIGNAL ;
    PORT
      LAYER M4 ;
        RECT  21.516 18.768 21.6 18.792 ;
    END
  END o[156]
  PIN o[157]
    DIRECTION OUTPUT ;
    USE SIGNAL ;
    PORT
      LAYER M4 ;
        RECT  21.516 18.864 21.6 18.888 ;
    END
  END o[157]
  PIN o[158]
    DIRECTION OUTPUT ;
    USE SIGNAL ;
    PORT
      LAYER M4 ;
        RECT  21.516 18.96 21.6 18.984 ;
    END
  END o[158]
  PIN o[159]
    DIRECTION OUTPUT ;
    USE SIGNAL ;
    PORT
      LAYER M4 ;
        RECT  21.516 19.056 21.6 19.08 ;
    END
  END o[159]
  PIN o[15]
    DIRECTION OUTPUT ;
    USE SIGNAL ;
    PORT
      LAYER M4 ;
        RECT  21.516 11.376 21.6 11.4 ;
    END
  END o[15]
  PIN o[160]
    DIRECTION OUTPUT ;
    USE SIGNAL ;
    PORT
      LAYER M4 ;
        RECT  21.516 6.864 21.6 6.888 ;
    END
  END o[160]
  PIN o[161]
    DIRECTION OUTPUT ;
    USE SIGNAL ;
    PORT
      LAYER M4 ;
        RECT  21.516 6.96 21.6 6.984 ;
    END
  END o[161]
  PIN o[162]
    DIRECTION OUTPUT ;
    USE SIGNAL ;
    PORT
      LAYER M4 ;
        RECT  21.516 7.056 21.6 7.08 ;
    END
  END o[162]
  PIN o[163]
    DIRECTION OUTPUT ;
    USE SIGNAL ;
    PORT
      LAYER M4 ;
        RECT  21.516 7.152 21.6 7.176 ;
    END
  END o[163]
  PIN o[164]
    DIRECTION OUTPUT ;
    USE SIGNAL ;
    PORT
      LAYER M4 ;
        RECT  21.516 7.248 21.6 7.272 ;
    END
  END o[164]
  PIN o[165]
    DIRECTION OUTPUT ;
    USE SIGNAL ;
    PORT
      LAYER M4 ;
        RECT  21.516 7.344 21.6 7.368 ;
    END
  END o[165]
  PIN o[166]
    DIRECTION OUTPUT ;
    USE SIGNAL ;
    PORT
      LAYER M4 ;
        RECT  21.516 7.44 21.6 7.464 ;
    END
  END o[166]
  PIN o[167]
    DIRECTION OUTPUT ;
    USE SIGNAL ;
    PORT
      LAYER M4 ;
        RECT  21.516 7.536 21.6 7.56 ;
    END
  END o[167]
  PIN o[168]
    DIRECTION OUTPUT ;
    USE SIGNAL ;
    PORT
      LAYER M4 ;
        RECT  21.516 7.632 21.6 7.656 ;
    END
  END o[168]
  PIN o[169]
    DIRECTION OUTPUT ;
    USE SIGNAL ;
    PORT
      LAYER M4 ;
        RECT  21.516 7.728 21.6 7.752 ;
    END
  END o[169]
  PIN o[16]
    DIRECTION OUTPUT ;
    USE SIGNAL ;
    PORT
      LAYER M4 ;
        RECT  21.516 11.472 21.6 11.496 ;
    END
  END o[16]
  PIN o[170]
    DIRECTION OUTPUT ;
    USE SIGNAL ;
    PORT
      LAYER M4 ;
        RECT  21.516 7.824 21.6 7.848 ;
    END
  END o[170]
  PIN o[171]
    DIRECTION OUTPUT ;
    USE SIGNAL ;
    PORT
      LAYER M4 ;
        RECT  21.516 7.92 21.6 7.944 ;
    END
  END o[171]
  PIN o[172]
    DIRECTION OUTPUT ;
    USE SIGNAL ;
    PORT
      LAYER M4 ;
        RECT  21.516 8.016 21.6 8.04 ;
    END
  END o[172]
  PIN o[173]
    DIRECTION OUTPUT ;
    USE SIGNAL ;
    PORT
      LAYER M4 ;
        RECT  21.516 8.112 21.6 8.136 ;
    END
  END o[173]
  PIN o[174]
    DIRECTION OUTPUT ;
    USE SIGNAL ;
    PORT
      LAYER M4 ;
        RECT  21.516 8.208 21.6 8.232 ;
    END
  END o[174]
  PIN o[175]
    DIRECTION OUTPUT ;
    USE SIGNAL ;
    PORT
      LAYER M4 ;
        RECT  21.516 8.304 21.6 8.328 ;
    END
  END o[175]
  PIN o[176]
    DIRECTION OUTPUT ;
    USE SIGNAL ;
    PORT
      LAYER M4 ;
        RECT  21.516 8.4 21.6 8.424 ;
    END
  END o[176]
  PIN o[177]
    DIRECTION OUTPUT ;
    USE SIGNAL ;
    PORT
      LAYER M4 ;
        RECT  21.516 8.496 21.6 8.52 ;
    END
  END o[177]
  PIN o[178]
    DIRECTION OUTPUT ;
    USE SIGNAL ;
    PORT
      LAYER M4 ;
        RECT  21.516 8.592 21.6 8.616 ;
    END
  END o[178]
  PIN o[179]
    DIRECTION OUTPUT ;
    USE SIGNAL ;
    PORT
      LAYER M4 ;
        RECT  21.516 8.688 21.6 8.712 ;
    END
  END o[179]
  PIN o[17]
    DIRECTION OUTPUT ;
    USE SIGNAL ;
    PORT
      LAYER M4 ;
        RECT  21.516 11.568 21.6 11.592 ;
    END
  END o[17]
  PIN o[180]
    DIRECTION OUTPUT ;
    USE SIGNAL ;
    PORT
      LAYER M4 ;
        RECT  21.516 8.784 21.6 8.808 ;
    END
  END o[180]
  PIN o[181]
    DIRECTION OUTPUT ;
    USE SIGNAL ;
    PORT
      LAYER M4 ;
        RECT  21.516 8.88 21.6 8.904 ;
    END
  END o[181]
  PIN o[182]
    DIRECTION OUTPUT ;
    USE SIGNAL ;
    PORT
      LAYER M4 ;
        RECT  21.516 8.976 21.6 9 ;
    END
  END o[182]
  PIN o[183]
    DIRECTION OUTPUT ;
    USE SIGNAL ;
    PORT
      LAYER M4 ;
        RECT  21.516 9.072 21.6 9.096 ;
    END
  END o[183]
  PIN o[184]
    DIRECTION OUTPUT ;
    USE SIGNAL ;
    PORT
      LAYER M4 ;
        RECT  21.516 9.168 21.6 9.192 ;
    END
  END o[184]
  PIN o[185]
    DIRECTION OUTPUT ;
    USE SIGNAL ;
    PORT
      LAYER M4 ;
        RECT  21.516 9.264 21.6 9.288 ;
    END
  END o[185]
  PIN o[186]
    DIRECTION OUTPUT ;
    USE SIGNAL ;
    PORT
      LAYER M4 ;
        RECT  21.516 9.36 21.6 9.384 ;
    END
  END o[186]
  PIN o[187]
    DIRECTION OUTPUT ;
    USE SIGNAL ;
    PORT
      LAYER M4 ;
        RECT  21.516 9.456 21.6 9.48 ;
    END
  END o[187]
  PIN o[188]
    DIRECTION OUTPUT ;
    USE SIGNAL ;
    PORT
      LAYER M4 ;
        RECT  21.516 9.552 21.6 9.576 ;
    END
  END o[188]
  PIN o[189]
    DIRECTION OUTPUT ;
    USE SIGNAL ;
    PORT
      LAYER M4 ;
        RECT  21.516 9.648 21.6 9.672 ;
    END
  END o[189]
  PIN o[18]
    DIRECTION OUTPUT ;
    USE SIGNAL ;
    PORT
      LAYER M4 ;
        RECT  21.516 11.664 21.6 11.688 ;
    END
  END o[18]
  PIN o[190]
    DIRECTION OUTPUT ;
    USE SIGNAL ;
    PORT
      LAYER M4 ;
        RECT  21.516 9.744 21.6 9.768 ;
    END
  END o[190]
  PIN o[191]
    DIRECTION OUTPUT ;
    USE SIGNAL ;
    PORT
      LAYER M4 ;
        RECT  21.516 9.84 21.6 9.864 ;
    END
  END o[191]
  PIN o[192]
    DIRECTION OUTPUT ;
    USE SIGNAL ;
    PORT
      LAYER M4 ;
        RECT  21.516 19.92 21.6 19.944 ;
    END
  END o[192]
  PIN o[193]
    DIRECTION OUTPUT ;
    USE SIGNAL ;
    PORT
      LAYER M4 ;
        RECT  21.516 20.016 21.6 20.04 ;
    END
  END o[193]
  PIN o[194]
    DIRECTION OUTPUT ;
    USE SIGNAL ;
    PORT
      LAYER M4 ;
        RECT  21.516 20.112 21.6 20.136 ;
    END
  END o[194]
  PIN o[195]
    DIRECTION OUTPUT ;
    USE SIGNAL ;
    PORT
      LAYER M4 ;
        RECT  21.516 20.208 21.6 20.232 ;
    END
  END o[195]
  PIN o[196]
    DIRECTION OUTPUT ;
    USE SIGNAL ;
    PORT
      LAYER M4 ;
        RECT  21.516 20.304 21.6 20.328 ;
    END
  END o[196]
  PIN o[197]
    DIRECTION OUTPUT ;
    USE SIGNAL ;
    PORT
      LAYER M4 ;
        RECT  21.516 20.4 21.6 20.424 ;
    END
  END o[197]
  PIN o[198]
    DIRECTION OUTPUT ;
    USE SIGNAL ;
    PORT
      LAYER M4 ;
        RECT  21.516 20.496 21.6 20.52 ;
    END
  END o[198]
  PIN o[199]
    DIRECTION OUTPUT ;
    USE SIGNAL ;
    PORT
      LAYER M4 ;
        RECT  21.516 20.592 21.6 20.616 ;
    END
  END o[199]
  PIN o[19]
    DIRECTION OUTPUT ;
    USE SIGNAL ;
    PORT
      LAYER M4 ;
        RECT  21.516 11.76 21.6 11.784 ;
    END
  END o[19]
  PIN o[1]
    DIRECTION OUTPUT ;
    USE SIGNAL ;
    PORT
      LAYER M4 ;
        RECT  21.516 10.032 21.6 10.056 ;
    END
  END o[1]
  PIN o[200]
    DIRECTION OUTPUT ;
    USE SIGNAL ;
    PORT
      LAYER M4 ;
        RECT  21.516 20.688 21.6 20.712 ;
    END
  END o[200]
  PIN o[201]
    DIRECTION OUTPUT ;
    USE SIGNAL ;
    PORT
      LAYER M4 ;
        RECT  21.516 20.784 21.6 20.808 ;
    END
  END o[201]
  PIN o[202]
    DIRECTION OUTPUT ;
    USE SIGNAL ;
    PORT
      LAYER M4 ;
        RECT  21.516 20.88 21.6 20.904 ;
    END
  END o[202]
  PIN o[203]
    DIRECTION OUTPUT ;
    USE SIGNAL ;
    PORT
      LAYER M4 ;
        RECT  21.516 20.976 21.6 21 ;
    END
  END o[203]
  PIN o[204]
    DIRECTION OUTPUT ;
    USE SIGNAL ;
    PORT
      LAYER M4 ;
        RECT  21.516 21.072 21.6 21.096 ;
    END
  END o[204]
  PIN o[205]
    DIRECTION OUTPUT ;
    USE SIGNAL ;
    PORT
      LAYER M4 ;
        RECT  21.516 21.168 21.6 21.192 ;
    END
  END o[205]
  PIN o[206]
    DIRECTION OUTPUT ;
    USE SIGNAL ;
    PORT
      LAYER M4 ;
        RECT  21.516 21.264 21.6 21.288 ;
    END
  END o[206]
  PIN o[207]
    DIRECTION OUTPUT ;
    USE SIGNAL ;
    PORT
      LAYER M4 ;
        RECT  21.516 21.36 21.6 21.384 ;
    END
  END o[207]
  PIN o[208]
    DIRECTION OUTPUT ;
    USE SIGNAL ;
    PORT
      LAYER M4 ;
        RECT  21.516 21.456 21.6 21.48 ;
    END
  END o[208]
  PIN o[209]
    DIRECTION OUTPUT ;
    USE SIGNAL ;
    PORT
      LAYER M4 ;
        RECT  21.516 21.552 21.6 21.576 ;
    END
  END o[209]
  PIN o[20]
    DIRECTION OUTPUT ;
    USE SIGNAL ;
    PORT
      LAYER M4 ;
        RECT  21.516 11.856 21.6 11.88 ;
    END
  END o[20]
  PIN o[210]
    DIRECTION OUTPUT ;
    USE SIGNAL ;
    PORT
      LAYER M4 ;
        RECT  21.516 21.648 21.6 21.672 ;
    END
  END o[210]
  PIN o[211]
    DIRECTION OUTPUT ;
    USE SIGNAL ;
    PORT
      LAYER M4 ;
        RECT  21.516 21.744 21.6 21.768 ;
    END
  END o[211]
  PIN o[212]
    DIRECTION OUTPUT ;
    USE SIGNAL ;
    PORT
      LAYER M4 ;
        RECT  21.516 21.84 21.6 21.864 ;
    END
  END o[212]
  PIN o[213]
    DIRECTION OUTPUT ;
    USE SIGNAL ;
    PORT
      LAYER M4 ;
        RECT  21.516 21.936 21.6 21.96 ;
    END
  END o[213]
  PIN o[214]
    DIRECTION OUTPUT ;
    USE SIGNAL ;
    PORT
      LAYER M4 ;
        RECT  21.516 22.032 21.6 22.056 ;
    END
  END o[214]
  PIN o[215]
    DIRECTION OUTPUT ;
    USE SIGNAL ;
    PORT
      LAYER M4 ;
        RECT  21.516 22.128 21.6 22.152 ;
    END
  END o[215]
  PIN o[216]
    DIRECTION OUTPUT ;
    USE SIGNAL ;
    PORT
      LAYER M4 ;
        RECT  21.516 22.224 21.6 22.248 ;
    END
  END o[216]
  PIN o[217]
    DIRECTION OUTPUT ;
    USE SIGNAL ;
    PORT
      LAYER M4 ;
        RECT  21.516 22.32 21.6 22.344 ;
    END
  END o[217]
  PIN o[218]
    DIRECTION OUTPUT ;
    USE SIGNAL ;
    PORT
      LAYER M4 ;
        RECT  21.516 22.416 21.6 22.44 ;
    END
  END o[218]
  PIN o[219]
    DIRECTION OUTPUT ;
    USE SIGNAL ;
    PORT
      LAYER M4 ;
        RECT  21.516 22.512 21.6 22.536 ;
    END
  END o[219]
  PIN o[21]
    DIRECTION OUTPUT ;
    USE SIGNAL ;
    PORT
      LAYER M4 ;
        RECT  21.516 11.952 21.6 11.976 ;
    END
  END o[21]
  PIN o[220]
    DIRECTION OUTPUT ;
    USE SIGNAL ;
    PORT
      LAYER M4 ;
        RECT  21.516 22.608 21.6 22.632 ;
    END
  END o[220]
  PIN o[221]
    DIRECTION OUTPUT ;
    USE SIGNAL ;
    PORT
      LAYER M4 ;
        RECT  21.516 22.704 21.6 22.728 ;
    END
  END o[221]
  PIN o[222]
    DIRECTION OUTPUT ;
    USE SIGNAL ;
    PORT
      LAYER M4 ;
        RECT  21.516 22.8 21.6 22.824 ;
    END
  END o[222]
  PIN o[223]
    DIRECTION OUTPUT ;
    USE SIGNAL ;
    PORT
      LAYER M4 ;
        RECT  21.516 22.896 21.6 22.92 ;
    END
  END o[223]
  PIN o[224]
    DIRECTION OUTPUT ;
    USE SIGNAL ;
    PORT
      LAYER M4 ;
        RECT  21.516 22.992 21.6 23.016 ;
    END
  END o[224]
  PIN o[225]
    DIRECTION OUTPUT ;
    USE SIGNAL ;
    PORT
      LAYER M4 ;
        RECT  21.516 23.088 21.6 23.112 ;
    END
  END o[225]
  PIN o[226]
    DIRECTION OUTPUT ;
    USE SIGNAL ;
    PORT
      LAYER M4 ;
        RECT  21.516 23.184 21.6 23.208 ;
    END
  END o[226]
  PIN o[227]
    DIRECTION OUTPUT ;
    USE SIGNAL ;
    PORT
      LAYER M4 ;
        RECT  21.516 23.28 21.6 23.304 ;
    END
  END o[227]
  PIN o[228]
    DIRECTION OUTPUT ;
    USE SIGNAL ;
    PORT
      LAYER M4 ;
        RECT  21.516 23.376 21.6 23.4 ;
    END
  END o[228]
  PIN o[229]
    DIRECTION OUTPUT ;
    USE SIGNAL ;
    PORT
      LAYER M4 ;
        RECT  21.516 23.472 21.6 23.496 ;
    END
  END o[229]
  PIN o[22]
    DIRECTION OUTPUT ;
    USE SIGNAL ;
    PORT
      LAYER M4 ;
        RECT  21.516 12.048 21.6 12.072 ;
    END
  END o[22]
  PIN o[230]
    DIRECTION OUTPUT ;
    USE SIGNAL ;
    PORT
      LAYER M4 ;
        RECT  21.516 23.568 21.6 23.592 ;
    END
  END o[230]
  PIN o[231]
    DIRECTION OUTPUT ;
    USE SIGNAL ;
    PORT
      LAYER M4 ;
        RECT  21.516 23.664 21.6 23.688 ;
    END
  END o[231]
  PIN o[232]
    DIRECTION OUTPUT ;
    USE SIGNAL ;
    PORT
      LAYER M4 ;
        RECT  21.516 23.76 21.6 23.784 ;
    END
  END o[232]
  PIN o[233]
    DIRECTION OUTPUT ;
    USE SIGNAL ;
    PORT
      LAYER M4 ;
        RECT  21.516 23.856 21.6 23.88 ;
    END
  END o[233]
  PIN o[234]
    DIRECTION OUTPUT ;
    USE SIGNAL ;
    PORT
      LAYER M4 ;
        RECT  21.516 23.952 21.6 23.976 ;
    END
  END o[234]
  PIN o[235]
    DIRECTION OUTPUT ;
    USE SIGNAL ;
    PORT
      LAYER M4 ;
        RECT  21.516 24.048 21.6 24.072 ;
    END
  END o[235]
  PIN o[236]
    DIRECTION OUTPUT ;
    USE SIGNAL ;
    PORT
      LAYER M4 ;
        RECT  21.516 24.144 21.6 24.168 ;
    END
  END o[236]
  PIN o[237]
    DIRECTION OUTPUT ;
    USE SIGNAL ;
    PORT
      LAYER M4 ;
        RECT  21.516 24.24 21.6 24.264 ;
    END
  END o[237]
  PIN o[238]
    DIRECTION OUTPUT ;
    USE SIGNAL ;
    PORT
      LAYER M4 ;
        RECT  21.516 24.336 21.6 24.36 ;
    END
  END o[238]
  PIN o[239]
    DIRECTION OUTPUT ;
    USE SIGNAL ;
    PORT
      LAYER M4 ;
        RECT  21.516 24.432 21.6 24.456 ;
    END
  END o[239]
  PIN o[23]
    DIRECTION OUTPUT ;
    USE SIGNAL ;
    PORT
      LAYER M4 ;
        RECT  21.516 12.144 21.6 12.168 ;
    END
  END o[23]
  PIN o[240]
    DIRECTION OUTPUT ;
    USE SIGNAL ;
    PORT
      LAYER M4 ;
        RECT  21.516 24.528 21.6 24.552 ;
    END
  END o[240]
  PIN o[241]
    DIRECTION OUTPUT ;
    USE SIGNAL ;
    PORT
      LAYER M4 ;
        RECT  21.516 24.624 21.6 24.648 ;
    END
  END o[241]
  PIN o[242]
    DIRECTION OUTPUT ;
    USE SIGNAL ;
    PORT
      LAYER M4 ;
        RECT  21.516 24.72 21.6 24.744 ;
    END
  END o[242]
  PIN o[243]
    DIRECTION OUTPUT ;
    USE SIGNAL ;
    PORT
      LAYER M4 ;
        RECT  21.516 24.816 21.6 24.84 ;
    END
  END o[243]
  PIN o[244]
    DIRECTION OUTPUT ;
    USE SIGNAL ;
    PORT
      LAYER M4 ;
        RECT  21.516 24.912 21.6 24.936 ;
    END
  END o[244]
  PIN o[245]
    DIRECTION OUTPUT ;
    USE SIGNAL ;
    PORT
      LAYER M4 ;
        RECT  21.516 25.008 21.6 25.032 ;
    END
  END o[245]
  PIN o[246]
    DIRECTION OUTPUT ;
    USE SIGNAL ;
    PORT
      LAYER M4 ;
        RECT  21.516 25.104 21.6 25.128 ;
    END
  END o[246]
  PIN o[247]
    DIRECTION OUTPUT ;
    USE SIGNAL ;
    PORT
      LAYER M4 ;
        RECT  21.516 25.2 21.6 25.224 ;
    END
  END o[247]
  PIN o[248]
    DIRECTION OUTPUT ;
    USE SIGNAL ;
    PORT
      LAYER M4 ;
        RECT  21.516 25.296 21.6 25.32 ;
    END
  END o[248]
  PIN o[249]
    DIRECTION OUTPUT ;
    USE SIGNAL ;
    PORT
      LAYER M4 ;
        RECT  21.516 25.392 21.6 25.416 ;
    END
  END o[249]
  PIN o[24]
    DIRECTION OUTPUT ;
    USE SIGNAL ;
    PORT
      LAYER M4 ;
        RECT  21.516 12.24 21.6 12.264 ;
    END
  END o[24]
  PIN o[250]
    DIRECTION OUTPUT ;
    USE SIGNAL ;
    PORT
      LAYER M4 ;
        RECT  21.516 25.488 21.6 25.512 ;
    END
  END o[250]
  PIN o[251]
    DIRECTION OUTPUT ;
    USE SIGNAL ;
    PORT
      LAYER M4 ;
        RECT  21.516 25.584 21.6 25.608 ;
    END
  END o[251]
  PIN o[252]
    DIRECTION OUTPUT ;
    USE SIGNAL ;
    PORT
      LAYER M4 ;
        RECT  21.516 25.68 21.6 25.704 ;
    END
  END o[252]
  PIN o[253]
    DIRECTION OUTPUT ;
    USE SIGNAL ;
    PORT
      LAYER M4 ;
        RECT  21.516 25.776 21.6 25.8 ;
    END
  END o[253]
  PIN o[254]
    DIRECTION OUTPUT ;
    USE SIGNAL ;
    PORT
      LAYER M4 ;
        RECT  21.516 25.872 21.6 25.896 ;
    END
  END o[254]
  PIN o[255]
    DIRECTION OUTPUT ;
    USE SIGNAL ;
    PORT
      LAYER M4 ;
        RECT  21.516 25.968 21.6 25.992 ;
    END
  END o[255]
  PIN o[256]
    DIRECTION OUTPUT ;
    USE SIGNAL ;
    PORT
      LAYER M4 ;
        RECT  21.516 26.064 21.6 26.088 ;
    END
  END o[256]
  PIN o[257]
    DIRECTION OUTPUT ;
    USE SIGNAL ;
    PORT
      LAYER M4 ;
        RECT  21.516 26.16 21.6 26.184 ;
    END
  END o[257]
  PIN o[258]
    DIRECTION OUTPUT ;
    USE SIGNAL ;
    PORT
      LAYER M4 ;
        RECT  21.516 26.256 21.6 26.28 ;
    END
  END o[258]
  PIN o[259]
    DIRECTION OUTPUT ;
    USE SIGNAL ;
    PORT
      LAYER M4 ;
        RECT  21.516 26.352 21.6 26.376 ;
    END
  END o[259]
  PIN o[25]
    DIRECTION OUTPUT ;
    USE SIGNAL ;
    PORT
      LAYER M4 ;
        RECT  21.516 12.336 21.6 12.36 ;
    END
  END o[25]
  PIN o[260]
    DIRECTION OUTPUT ;
    USE SIGNAL ;
    PORT
      LAYER M4 ;
        RECT  21.516 26.448 21.6 26.472 ;
    END
  END o[260]
  PIN o[261]
    DIRECTION OUTPUT ;
    USE SIGNAL ;
    PORT
      LAYER M4 ;
        RECT  21.516 26.544 21.6 26.568 ;
    END
  END o[261]
  PIN o[262]
    DIRECTION OUTPUT ;
    USE SIGNAL ;
    PORT
      LAYER M4 ;
        RECT  21.516 26.64 21.6 26.664 ;
    END
  END o[262]
  PIN o[263]
    DIRECTION OUTPUT ;
    USE SIGNAL ;
    PORT
      LAYER M4 ;
        RECT  21.516 26.736 21.6 26.76 ;
    END
  END o[263]
  PIN o[264]
    DIRECTION OUTPUT ;
    USE SIGNAL ;
    PORT
      LAYER M4 ;
        RECT  21.516 26.832 21.6 26.856 ;
    END
  END o[264]
  PIN o[265]
    DIRECTION OUTPUT ;
    USE SIGNAL ;
    PORT
      LAYER M4 ;
        RECT  21.516 26.928 21.6 26.952 ;
    END
  END o[265]
  PIN o[266]
    DIRECTION OUTPUT ;
    USE SIGNAL ;
    PORT
      LAYER M4 ;
        RECT  21.516 27.024 21.6 27.048 ;
    END
  END o[266]
  PIN o[267]
    DIRECTION OUTPUT ;
    USE SIGNAL ;
    PORT
      LAYER M4 ;
        RECT  21.516 27.12 21.6 27.144 ;
    END
  END o[267]
  PIN o[268]
    DIRECTION OUTPUT ;
    USE SIGNAL ;
    PORT
      LAYER M4 ;
        RECT  21.516 27.216 21.6 27.24 ;
    END
  END o[268]
  PIN o[269]
    DIRECTION OUTPUT ;
    USE SIGNAL ;
    PORT
      LAYER M4 ;
        RECT  21.516 27.312 21.6 27.336 ;
    END
  END o[269]
  PIN o[26]
    DIRECTION OUTPUT ;
    USE SIGNAL ;
    PORT
      LAYER M4 ;
        RECT  21.516 12.432 21.6 12.456 ;
    END
  END o[26]
  PIN o[270]
    DIRECTION OUTPUT ;
    USE SIGNAL ;
    PORT
      LAYER M4 ;
        RECT  21.516 27.408 21.6 27.432 ;
    END
  END o[270]
  PIN o[271]
    DIRECTION OUTPUT ;
    USE SIGNAL ;
    PORT
      LAYER M4 ;
        RECT  21.516 27.504 21.6 27.528 ;
    END
  END o[271]
  PIN o[272]
    DIRECTION OUTPUT ;
    USE SIGNAL ;
    PORT
      LAYER M4 ;
        RECT  21.516 27.6 21.6 27.624 ;
    END
  END o[272]
  PIN o[273]
    DIRECTION OUTPUT ;
    USE SIGNAL ;
    PORT
      LAYER M4 ;
        RECT  21.516 27.696 21.6 27.72 ;
    END
  END o[273]
  PIN o[274]
    DIRECTION OUTPUT ;
    USE SIGNAL ;
    PORT
      LAYER M4 ;
        RECT  21.516 27.792 21.6 27.816 ;
    END
  END o[274]
  PIN o[275]
    DIRECTION OUTPUT ;
    USE SIGNAL ;
    PORT
      LAYER M4 ;
        RECT  21.516 27.888 21.6 27.912 ;
    END
  END o[275]
  PIN o[276]
    DIRECTION OUTPUT ;
    USE SIGNAL ;
    PORT
      LAYER M4 ;
        RECT  21.516 27.984 21.6 28.008 ;
    END
  END o[276]
  PIN o[277]
    DIRECTION OUTPUT ;
    USE SIGNAL ;
    PORT
      LAYER M4 ;
        RECT  21.516 28.08 21.6 28.104 ;
    END
  END o[277]
  PIN o[278]
    DIRECTION OUTPUT ;
    USE SIGNAL ;
    PORT
      LAYER M4 ;
        RECT  21.516 28.176 21.6 28.2 ;
    END
  END o[278]
  PIN o[279]
    DIRECTION OUTPUT ;
    USE SIGNAL ;
    PORT
      LAYER M4 ;
        RECT  21.516 28.272 21.6 28.296 ;
    END
  END o[279]
  PIN o[27]
    DIRECTION OUTPUT ;
    USE SIGNAL ;
    PORT
      LAYER M4 ;
        RECT  21.516 12.528 21.6 12.552 ;
    END
  END o[27]
  PIN o[280]
    DIRECTION OUTPUT ;
    USE SIGNAL ;
    PORT
      LAYER M4 ;
        RECT  21.516 28.368 21.6 28.392 ;
    END
  END o[280]
  PIN o[281]
    DIRECTION OUTPUT ;
    USE SIGNAL ;
    PORT
      LAYER M4 ;
        RECT  21.516 28.464 21.6 28.488 ;
    END
  END o[281]
  PIN o[282]
    DIRECTION OUTPUT ;
    USE SIGNAL ;
    PORT
      LAYER M4 ;
        RECT  21.516 28.56 21.6 28.584 ;
    END
  END o[282]
  PIN o[28]
    DIRECTION OUTPUT ;
    USE SIGNAL ;
    PORT
      LAYER M4 ;
        RECT  21.516 12.624 21.6 12.648 ;
    END
  END o[28]
  PIN o[29]
    DIRECTION OUTPUT ;
    USE SIGNAL ;
    PORT
      LAYER M4 ;
        RECT  21.516 12.72 21.6 12.744 ;
    END
  END o[29]
  PIN o[2]
    DIRECTION OUTPUT ;
    USE SIGNAL ;
    PORT
      LAYER M4 ;
        RECT  21.516 10.128 21.6 10.152 ;
    END
  END o[2]
  PIN o[30]
    DIRECTION OUTPUT ;
    USE SIGNAL ;
    PORT
      LAYER M4 ;
        RECT  21.516 12.816 21.6 12.84 ;
    END
  END o[30]
  PIN o[31]
    DIRECTION OUTPUT ;
    USE SIGNAL ;
    PORT
      LAYER M4 ;
        RECT  21.516 12.912 21.6 12.936 ;
    END
  END o[31]
  PIN o[32]
    DIRECTION OUTPUT ;
    USE SIGNAL ;
    PORT
      LAYER M4 ;
        RECT  21.516 13.008 21.6 13.032 ;
    END
  END o[32]
  PIN o[33]
    DIRECTION OUTPUT ;
    USE SIGNAL ;
    PORT
      LAYER M4 ;
        RECT  21.516 13.104 21.6 13.128 ;
    END
  END o[33]
  PIN o[34]
    DIRECTION OUTPUT ;
    USE SIGNAL ;
    PORT
      LAYER M4 ;
        RECT  21.516 13.2 21.6 13.224 ;
    END
  END o[34]
  PIN o[35]
    DIRECTION OUTPUT ;
    USE SIGNAL ;
    PORT
      LAYER M4 ;
        RECT  21.516 13.296 21.6 13.32 ;
    END
  END o[35]
  PIN o[36]
    DIRECTION OUTPUT ;
    USE SIGNAL ;
    PORT
      LAYER M4 ;
        RECT  21.516 13.392 21.6 13.416 ;
    END
  END o[36]
  PIN o[37]
    DIRECTION OUTPUT ;
    USE SIGNAL ;
    PORT
      LAYER M4 ;
        RECT  21.516 13.488 21.6 13.512 ;
    END
  END o[37]
  PIN o[38]
    DIRECTION OUTPUT ;
    USE SIGNAL ;
    PORT
      LAYER M4 ;
        RECT  21.516 13.584 21.6 13.608 ;
    END
  END o[38]
  PIN o[39]
    DIRECTION OUTPUT ;
    USE SIGNAL ;
    PORT
      LAYER M4 ;
        RECT  21.516 13.68 21.6 13.704 ;
    END
  END o[39]
  PIN o[3]
    DIRECTION OUTPUT ;
    USE SIGNAL ;
    PORT
      LAYER M4 ;
        RECT  21.516 10.224 21.6 10.248 ;
    END
  END o[3]
  PIN o[40]
    DIRECTION OUTPUT ;
    USE SIGNAL ;
    PORT
      LAYER M4 ;
        RECT  21.516 13.776 21.6 13.8 ;
    END
  END o[40]
  PIN o[41]
    DIRECTION OUTPUT ;
    USE SIGNAL ;
    PORT
      LAYER M4 ;
        RECT  21.516 13.872 21.6 13.896 ;
    END
  END o[41]
  PIN o[42]
    DIRECTION OUTPUT ;
    USE SIGNAL ;
    PORT
      LAYER M4 ;
        RECT  21.516 13.968 21.6 13.992 ;
    END
  END o[42]
  PIN o[43]
    DIRECTION OUTPUT ;
    USE SIGNAL ;
    PORT
      LAYER M4 ;
        RECT  21.516 14.064 21.6 14.088 ;
    END
  END o[43]
  PIN o[44]
    DIRECTION OUTPUT ;
    USE SIGNAL ;
    PORT
      LAYER M4 ;
        RECT  21.516 14.16 21.6 14.184 ;
    END
  END o[44]
  PIN o[45]
    DIRECTION OUTPUT ;
    USE SIGNAL ;
    PORT
      LAYER M4 ;
        RECT  21.516 14.256 21.6 14.28 ;
    END
  END o[45]
  PIN o[46]
    DIRECTION OUTPUT ;
    USE SIGNAL ;
    PORT
      LAYER M4 ;
        RECT  21.516 14.352 21.6 14.376 ;
    END
  END o[46]
  PIN o[47]
    DIRECTION OUTPUT ;
    USE SIGNAL ;
    PORT
      LAYER M4 ;
        RECT  21.516 14.448 21.6 14.472 ;
    END
  END o[47]
  PIN o[48]
    DIRECTION OUTPUT ;
    USE SIGNAL ;
    PORT
      LAYER M4 ;
        RECT  21.516 14.544 21.6 14.568 ;
    END
  END o[48]
  PIN o[49]
    DIRECTION OUTPUT ;
    USE SIGNAL ;
    PORT
      LAYER M4 ;
        RECT  21.516 14.64 21.6 14.664 ;
    END
  END o[49]
  PIN o[4]
    DIRECTION OUTPUT ;
    USE SIGNAL ;
    PORT
      LAYER M4 ;
        RECT  21.516 10.32 21.6 10.344 ;
    END
  END o[4]
  PIN o[50]
    DIRECTION OUTPUT ;
    USE SIGNAL ;
    PORT
      LAYER M4 ;
        RECT  21.516 14.736 21.6 14.76 ;
    END
  END o[50]
  PIN o[51]
    DIRECTION OUTPUT ;
    USE SIGNAL ;
    PORT
      LAYER M4 ;
        RECT  21.516 14.832 21.6 14.856 ;
    END
  END o[51]
  PIN o[52]
    DIRECTION OUTPUT ;
    USE SIGNAL ;
    PORT
      LAYER M4 ;
        RECT  21.516 14.928 21.6 14.952 ;
    END
  END o[52]
  PIN o[53]
    DIRECTION OUTPUT ;
    USE SIGNAL ;
    PORT
      LAYER M4 ;
        RECT  21.516 15.024 21.6 15.048 ;
    END
  END o[53]
  PIN o[54]
    DIRECTION OUTPUT ;
    USE SIGNAL ;
    PORT
      LAYER M4 ;
        RECT  21.516 15.12 21.6 15.144 ;
    END
  END o[54]
  PIN o[55]
    DIRECTION OUTPUT ;
    USE SIGNAL ;
    PORT
      LAYER M4 ;
        RECT  21.516 15.216 21.6 15.24 ;
    END
  END o[55]
  PIN o[56]
    DIRECTION OUTPUT ;
    USE SIGNAL ;
    PORT
      LAYER M4 ;
        RECT  21.516 15.312 21.6 15.336 ;
    END
  END o[56]
  PIN o[57]
    DIRECTION OUTPUT ;
    USE SIGNAL ;
    PORT
      LAYER M4 ;
        RECT  21.516 15.408 21.6 15.432 ;
    END
  END o[57]
  PIN o[58]
    DIRECTION OUTPUT ;
    USE SIGNAL ;
    PORT
      LAYER M4 ;
        RECT  21.516 15.504 21.6 15.528 ;
    END
  END o[58]
  PIN o[59]
    DIRECTION OUTPUT ;
    USE SIGNAL ;
    PORT
      LAYER M4 ;
        RECT  21.516 15.6 21.6 15.624 ;
    END
  END o[59]
  PIN o[5]
    DIRECTION OUTPUT ;
    USE SIGNAL ;
    PORT
      LAYER M4 ;
        RECT  21.516 10.416 21.6 10.44 ;
    END
  END o[5]
  PIN o[60]
    DIRECTION OUTPUT ;
    USE SIGNAL ;
    PORT
      LAYER M4 ;
        RECT  21.516 15.696 21.6 15.72 ;
    END
  END o[60]
  PIN o[61]
    DIRECTION OUTPUT ;
    USE SIGNAL ;
    PORT
      LAYER M4 ;
        RECT  21.516 15.792 21.6 15.816 ;
    END
  END o[61]
  PIN o[62]
    DIRECTION OUTPUT ;
    USE SIGNAL ;
    PORT
      LAYER M4 ;
        RECT  21.516 15.888 21.6 15.912 ;
    END
  END o[62]
  PIN o[63]
    DIRECTION OUTPUT ;
    USE SIGNAL ;
    PORT
      LAYER M4 ;
        RECT  21.516 15.984 21.6 16.008 ;
    END
  END o[63]
  PIN o[64]
    DIRECTION OUTPUT ;
    USE SIGNAL ;
    PORT
      LAYER M4 ;
        RECT  21.516 0.72 21.6 0.744 ;
    END
  END o[64]
  PIN o[65]
    DIRECTION OUTPUT ;
    USE SIGNAL ;
    PORT
      LAYER M4 ;
        RECT  21.516 0.816 21.6 0.84 ;
    END
  END o[65]
  PIN o[66]
    DIRECTION OUTPUT ;
    USE SIGNAL ;
    PORT
      LAYER M4 ;
        RECT  21.516 0.912 21.6 0.936 ;
    END
  END o[66]
  PIN o[67]
    DIRECTION OUTPUT ;
    USE SIGNAL ;
    PORT
      LAYER M4 ;
        RECT  21.516 1.008 21.6 1.032 ;
    END
  END o[67]
  PIN o[68]
    DIRECTION OUTPUT ;
    USE SIGNAL ;
    PORT
      LAYER M4 ;
        RECT  21.516 1.104 21.6 1.128 ;
    END
  END o[68]
  PIN o[69]
    DIRECTION OUTPUT ;
    USE SIGNAL ;
    PORT
      LAYER M4 ;
        RECT  21.516 1.2 21.6 1.224 ;
    END
  END o[69]
  PIN o[6]
    DIRECTION OUTPUT ;
    USE SIGNAL ;
    PORT
      LAYER M4 ;
        RECT  21.516 10.512 21.6 10.536 ;
    END
  END o[6]
  PIN o[70]
    DIRECTION OUTPUT ;
    USE SIGNAL ;
    PORT
      LAYER M4 ;
        RECT  21.516 1.296 21.6 1.32 ;
    END
  END o[70]
  PIN o[71]
    DIRECTION OUTPUT ;
    USE SIGNAL ;
    PORT
      LAYER M4 ;
        RECT  21.516 1.392 21.6 1.416 ;
    END
  END o[71]
  PIN o[72]
    DIRECTION OUTPUT ;
    USE SIGNAL ;
    PORT
      LAYER M4 ;
        RECT  21.516 1.488 21.6 1.512 ;
    END
  END o[72]
  PIN o[73]
    DIRECTION OUTPUT ;
    USE SIGNAL ;
    PORT
      LAYER M4 ;
        RECT  21.516 1.584 21.6 1.608 ;
    END
  END o[73]
  PIN o[74]
    DIRECTION OUTPUT ;
    USE SIGNAL ;
    PORT
      LAYER M4 ;
        RECT  21.516 1.68 21.6 1.704 ;
    END
  END o[74]
  PIN o[75]
    DIRECTION OUTPUT ;
    USE SIGNAL ;
    PORT
      LAYER M4 ;
        RECT  21.516 1.776 21.6 1.8 ;
    END
  END o[75]
  PIN o[76]
    DIRECTION OUTPUT ;
    USE SIGNAL ;
    PORT
      LAYER M4 ;
        RECT  21.516 1.872 21.6 1.896 ;
    END
  END o[76]
  PIN o[77]
    DIRECTION OUTPUT ;
    USE SIGNAL ;
    PORT
      LAYER M4 ;
        RECT  21.516 1.968 21.6 1.992 ;
    END
  END o[77]
  PIN o[78]
    DIRECTION OUTPUT ;
    USE SIGNAL ;
    PORT
      LAYER M4 ;
        RECT  21.516 2.064 21.6 2.088 ;
    END
  END o[78]
  PIN o[79]
    DIRECTION OUTPUT ;
    USE SIGNAL ;
    PORT
      LAYER M4 ;
        RECT  21.516 2.16 21.6 2.184 ;
    END
  END o[79]
  PIN o[7]
    DIRECTION OUTPUT ;
    USE SIGNAL ;
    PORT
      LAYER M4 ;
        RECT  21.516 10.608 21.6 10.632 ;
    END
  END o[7]
  PIN o[80]
    DIRECTION OUTPUT ;
    USE SIGNAL ;
    PORT
      LAYER M4 ;
        RECT  21.516 2.256 21.6 2.28 ;
    END
  END o[80]
  PIN o[81]
    DIRECTION OUTPUT ;
    USE SIGNAL ;
    PORT
      LAYER M4 ;
        RECT  21.516 2.352 21.6 2.376 ;
    END
  END o[81]
  PIN o[82]
    DIRECTION OUTPUT ;
    USE SIGNAL ;
    PORT
      LAYER M4 ;
        RECT  21.516 2.448 21.6 2.472 ;
    END
  END o[82]
  PIN o[83]
    DIRECTION OUTPUT ;
    USE SIGNAL ;
    PORT
      LAYER M4 ;
        RECT  21.516 2.544 21.6 2.568 ;
    END
  END o[83]
  PIN o[84]
    DIRECTION OUTPUT ;
    USE SIGNAL ;
    PORT
      LAYER M4 ;
        RECT  21.516 2.64 21.6 2.664 ;
    END
  END o[84]
  PIN o[85]
    DIRECTION OUTPUT ;
    USE SIGNAL ;
    PORT
      LAYER M4 ;
        RECT  21.516 2.736 21.6 2.76 ;
    END
  END o[85]
  PIN o[86]
    DIRECTION OUTPUT ;
    USE SIGNAL ;
    PORT
      LAYER M4 ;
        RECT  21.516 2.832 21.6 2.856 ;
    END
  END o[86]
  PIN o[87]
    DIRECTION OUTPUT ;
    USE SIGNAL ;
    PORT
      LAYER M4 ;
        RECT  21.516 2.928 21.6 2.952 ;
    END
  END o[87]
  PIN o[88]
    DIRECTION OUTPUT ;
    USE SIGNAL ;
    PORT
      LAYER M4 ;
        RECT  21.516 3.024 21.6 3.048 ;
    END
  END o[88]
  PIN o[89]
    DIRECTION OUTPUT ;
    USE SIGNAL ;
    PORT
      LAYER M4 ;
        RECT  21.516 3.12 21.6 3.144 ;
    END
  END o[89]
  PIN o[8]
    DIRECTION OUTPUT ;
    USE SIGNAL ;
    PORT
      LAYER M4 ;
        RECT  21.516 10.704 21.6 10.728 ;
    END
  END o[8]
  PIN o[90]
    DIRECTION OUTPUT ;
    USE SIGNAL ;
    PORT
      LAYER M4 ;
        RECT  21.516 3.216 21.6 3.24 ;
    END
  END o[90]
  PIN o[91]
    DIRECTION OUTPUT ;
    USE SIGNAL ;
    PORT
      LAYER M4 ;
        RECT  21.516 3.312 21.6 3.336 ;
    END
  END o[91]
  PIN o[92]
    DIRECTION OUTPUT ;
    USE SIGNAL ;
    PORT
      LAYER M4 ;
        RECT  21.516 3.408 21.6 3.432 ;
    END
  END o[92]
  PIN o[93]
    DIRECTION OUTPUT ;
    USE SIGNAL ;
    PORT
      LAYER M4 ;
        RECT  21.516 3.504 21.6 3.528 ;
    END
  END o[93]
  PIN o[94]
    DIRECTION OUTPUT ;
    USE SIGNAL ;
    PORT
      LAYER M4 ;
        RECT  21.516 3.6 21.6 3.624 ;
    END
  END o[94]
  PIN o[95]
    DIRECTION OUTPUT ;
    USE SIGNAL ;
    PORT
      LAYER M4 ;
        RECT  21.516 3.696 21.6 3.72 ;
    END
  END o[95]
  PIN o[96]
    DIRECTION OUTPUT ;
    USE SIGNAL ;
    PORT
      LAYER M4 ;
        RECT  21.516 3.792 21.6 3.816 ;
    END
  END o[96]
  PIN o[97]
    DIRECTION OUTPUT ;
    USE SIGNAL ;
    PORT
      LAYER M4 ;
        RECT  21.516 3.888 21.6 3.912 ;
    END
  END o[97]
  PIN o[98]
    DIRECTION OUTPUT ;
    USE SIGNAL ;
    PORT
      LAYER M4 ;
        RECT  21.516 3.984 21.6 4.008 ;
    END
  END o[98]
  PIN o[99]
    DIRECTION OUTPUT ;
    USE SIGNAL ;
    PORT
      LAYER M4 ;
        RECT  21.516 4.08 21.6 4.104 ;
    END
  END o[99]
  PIN o[9]
    DIRECTION OUTPUT ;
    USE SIGNAL ;
    PORT
      LAYER M4 ;
        RECT  21.516 10.8 21.6 10.824 ;
    END
  END o[9]
  PIN rs
    DIRECTION INPUT ;
    USE SIGNAL ;
    PORT
      LAYER M5 ;
        RECT  6.96 30.156 6.984 30.24 ;
    END
  END rs
  PIN VDD
    DIRECTION INOUT ;
    USE POWER ;
    PORT
      LAYER M5 ;
        RECT  18.792 2.151 18.912 28.089 ;
        RECT  13.392 2.151 13.512 28.089 ;
        RECT  7.992 2.151 8.112 28.089 ;
        RECT  2.592 2.151 2.712 28.089 ;
    END
  END VDD
  PIN VSS
    DIRECTION INOUT ;
    USE GROUND ;
    PORT
      LAYER M5 ;
        RECT  18.6 2.137 18.72 28.103 ;
        RECT  13.2 2.137 13.32 28.103 ;
        RECT  7.8 2.137 7.92 28.103 ;
        RECT  2.4 2.137 2.52 28.103 ;
    END
  END VSS
  OBS
    LAYER RVTN ;
     RECT  2.16 2.16 19.44 2.295 ;
     RECT  2.16 2.565 19.44 2.835 ;
     RECT  2.16 3.105 19.44 3.375 ;
     RECT  2.16 3.645 19.44 3.915 ;
     RECT  2.16 4.185 19.44 4.455 ;
     RECT  2.16 4.725 19.44 4.995 ;
     RECT  2.16 5.265 19.44 5.535 ;
     RECT  2.16 5.805 19.44 6.075 ;
     RECT  2.16 6.345 19.44 6.615 ;
     RECT  2.16 6.885 19.44 7.155 ;
     RECT  2.16 7.425 19.44 7.695 ;
     RECT  2.16 7.965 19.44 8.235 ;
     RECT  2.16 8.505 19.44 8.775 ;
     RECT  2.16 9.045 19.44 9.315 ;
     RECT  2.16 9.585 19.44 9.855 ;
     RECT  2.16 10.125 19.44 10.395 ;
     RECT  2.16 10.665 19.44 10.935 ;
     RECT  2.16 11.205 19.44 11.475 ;
     RECT  2.16 11.745 19.44 12.015 ;
     RECT  2.16 12.285 19.44 12.555 ;
     RECT  2.16 12.825 19.44 13.095 ;
     RECT  2.16 13.365 19.44 13.635 ;
     RECT  2.16 13.905 19.44 14.175 ;
     RECT  2.16 14.445 19.44 14.715 ;
     RECT  2.16 14.985 19.44 15.255 ;
     RECT  2.16 15.525 19.44 15.795 ;
     RECT  2.16 16.065 19.44 16.335 ;
     RECT  2.16 16.605 19.44 16.875 ;
     RECT  2.16 17.145 19.44 17.415 ;
     RECT  2.16 17.685 19.44 17.955 ;
     RECT  2.16 18.225 19.44 18.495 ;
     RECT  2.16 18.765 19.44 19.035 ;
     RECT  2.16 19.305 19.44 19.575 ;
     RECT  2.16 19.845 19.44 20.115 ;
     RECT  2.16 20.385 19.44 20.655 ;
     RECT  2.16 20.925 19.44 21.195 ;
     RECT  2.16 21.465 19.44 21.735 ;
     RECT  2.16 22.005 19.44 22.275 ;
     RECT  2.16 22.545 19.44 22.815 ;
     RECT  2.16 23.085 19.44 23.355 ;
     RECT  2.16 23.625 19.44 23.895 ;
     RECT  2.16 24.165 19.44 24.435 ;
     RECT  2.16 24.705 19.44 24.975 ;
     RECT  2.16 25.245 19.44 25.515 ;
     RECT  2.16 25.785 19.44 26.055 ;
     RECT  2.16 26.325 19.44 26.595 ;
     RECT  2.16 26.865 19.44 27.135 ;
     RECT  2.16 27.405 19.44 27.675 ;
     RECT  2.16 27.945 19.44 28.08 ;
    LAYER RVTP ;
     RECT  2.16 2.295 19.44 2.565 ;
     RECT  2.16 2.835 19.44 3.105 ;
     RECT  2.16 3.375 19.44 3.645 ;
     RECT  2.16 3.915 19.44 4.185 ;
     RECT  2.16 4.455 19.44 4.725 ;
     RECT  2.16 4.995 19.44 5.265 ;
     RECT  2.16 5.535 19.44 5.805 ;
     RECT  2.16 6.075 19.44 6.345 ;
     RECT  2.16 6.615 19.44 6.885 ;
     RECT  2.16 7.155 19.44 7.425 ;
     RECT  2.16 7.695 19.44 7.965 ;
     RECT  2.16 8.235 19.44 8.505 ;
     RECT  2.16 8.775 19.44 9.045 ;
     RECT  2.16 9.315 19.44 9.585 ;
     RECT  2.16 9.855 19.44 10.125 ;
     RECT  2.16 10.395 19.44 10.665 ;
     RECT  2.16 10.935 19.44 11.205 ;
     RECT  2.16 11.475 19.44 11.745 ;
     RECT  2.16 12.015 19.44 12.285 ;
     RECT  2.16 12.555 19.44 12.825 ;
     RECT  2.16 13.095 19.44 13.365 ;
     RECT  2.16 13.635 19.44 13.905 ;
     RECT  2.16 14.175 19.44 14.445 ;
     RECT  2.16 14.715 19.44 14.985 ;
     RECT  2.16 15.255 19.44 15.525 ;
     RECT  2.16 15.795 19.44 16.065 ;
     RECT  2.16 16.335 19.44 16.605 ;
     RECT  2.16 16.875 19.44 17.145 ;
     RECT  2.16 17.415 19.44 17.685 ;
     RECT  2.16 17.955 19.44 18.225 ;
     RECT  2.16 18.495 19.44 18.765 ;
     RECT  2.16 19.035 19.44 19.305 ;
     RECT  2.16 19.575 19.44 19.845 ;
     RECT  2.16 20.115 19.44 20.385 ;
     RECT  2.16 20.655 19.44 20.925 ;
     RECT  2.16 21.195 19.44 21.465 ;
     RECT  2.16 21.735 19.44 22.005 ;
     RECT  2.16 22.275 19.44 22.545 ;
     RECT  2.16 22.815 19.44 23.085 ;
     RECT  2.16 23.355 19.44 23.625 ;
     RECT  2.16 23.895 19.44 24.165 ;
     RECT  2.16 24.435 19.44 24.705 ;
     RECT  2.16 24.975 19.44 25.245 ;
     RECT  2.16 25.515 19.44 25.785 ;
     RECT  2.16 26.055 19.44 26.325 ;
     RECT  2.16 26.595 19.44 26.865 ;
     RECT  2.16 27.135 19.44 27.405 ;
     RECT  2.16 27.675 19.44 27.945 ;
    LAYER M1 ;
     RECT  2.16 2.151 19.44 28.089 ;
    LAYER M2 ;
     RECT  0.031 14.148 0.103 14.166 ;
     RECT  0.031 16.308 0.139 16.326 ;
     RECT  0.103 17.082 0.139 17.478 ;
     RECT  0.103 19.35 0.139 19.368 ;
     RECT  0.103 20.43 0.139 20.448 ;
     RECT  0.103 21.402 0.139 21.42 ;
     RECT  0.103 22.212 0.139 23.31 ;
     RECT  0.103 25.56 0.139 26.046 ;
     RECT  0.103 10.062 0.175 10.458 ;
     RECT  0.103 11.556 0.175 12.042 ;
     RECT  0.103 14.148 0.175 14.238 ;
     RECT  0.103 15.3 0.175 15.552 ;
     RECT  0.139 19.35 0.175 20.448 ;
     RECT  0.139 21.402 0.175 23.31 ;
     RECT  0.139 25.488 0.175 26.118 ;
     RECT  0.175 10.062 0.203 12.042 ;
     RECT  0.175 7.902 0.211 7.92 ;
     RECT  0.175 25.488 0.275 26.154 ;
     RECT  0.203 12.024 0.347 12.042 ;
     RECT  0.275 25.83 0.347 26.154 ;
     RECT  0.175 19.35 0.463 23.31 ;
     RECT  0.175 15.192 0.499 15.552 ;
     RECT  0.139 16.308 0.499 17.676 ;
     RECT  0.211 7.902 0.535 7.956 ;
     RECT  0.463 19.044 0.535 23.31 ;
     RECT  0.103 24.372 0.535 24.39 ;
     RECT  0.139 6.318 1.147 6.336 ;
     RECT  0.535 18.576 1.183 24.498 ;
     RECT  1.147 5.661 1.427 6.408 ;
     RECT  0.203 10.062 1.435 11.232 ;
     RECT  1.435 10.062 1.543 11.772 ;
     RECT  1.399 12.762 1.543 12.78 ;
     RECT  1.183 18.576 1.651 25.038 ;
     RECT  0.347 25.83 1.651 26.118 ;
     RECT  0.535 27.306 1.687 27.324 ;
     RECT  1.651 18.576 1.723 26.118 ;
     RECT  1.687 27.306 1.723 27.666 ;
     RECT  1.723 2.232 1.759 2.25 ;
     RECT  0.175 13.95 1.975 14.238 ;
     RECT  1.543 10.062 2.083 12.78 ;
     RECT  1.975 13.572 2.083 14.238 ;
     RECT  1.759 2.106 2.155 2.25 ;
     RECT  1.543 3.114 2.155 3.132 ;
     RECT  2.155 2.106 2.16 3.132 ;
     RECT  1.723 4.77 2.16 4.788 ;
     RECT  1.427 6.39 2.16 6.408 ;
     RECT  0.535 7.74 2.16 7.956 ;
     RECT  0.823 8.712 2.16 8.73 ;
     RECT  2.083 10.062 2.16 14.238 ;
     RECT  0.499 15.192 2.16 17.676 ;
     RECT  1.723 18.576 2.16 27.666 ;
     RECT  2.16 2.106 2.659 28.089 ;
     RECT  2.659 1.962 2.875 28.089 ;
     RECT  2.875 1.836 4.487 28.089 ;
     RECT  4.487 1.881 6.647 28.089 ;
     RECT  6.647 2.151 14.215 28.089 ;
     RECT  14.215 1.881 16.159 28.089 ;
     RECT  16.159 1.764 18.239 28.089 ;
     RECT  18.239 1.926 18.347 28.089 ;
     RECT  18.347 2.034 18.563 28.089 ;
     RECT  18.563 2.151 19.44 28.089 ;
     RECT  19.44 2.574 19.967 27.774 ;
     RECT  19.967 2.574 20.399 24.264 ;
     RECT  20.399 2.574 20.435 4.284 ;
     RECT  20.435 2.61 20.471 4.284 ;
     RECT  20.399 5.166 20.471 24.264 ;
     RECT  20.471 2.736 20.507 4.284 ;
     RECT  20.471 5.166 20.507 6.408 ;
     RECT  20.471 7.164 20.507 13.662 ;
     RECT  20.471 14.454 20.507 16.902 ;
     RECT  20.471 17.73 20.507 24.264 ;
     RECT  19.967 25.146 20.507 27.774 ;
     RECT  20.507 10.296 20.543 11.124 ;
     RECT  20.507 11.916 20.543 12.312 ;
     RECT  20.507 14.652 20.543 14.67 ;
     RECT  20.507 15.534 20.543 16.902 ;
     RECT  20.507 19.314 20.543 24.264 ;
     RECT  20.507 27.684 20.543 27.702 ;
     RECT  20.543 20.052 20.579 23.346 ;
     RECT  20.543 15.534 20.615 16.164 ;
     RECT  20.579 20.052 20.615 21.96 ;
     RECT  20.543 24.246 20.615 24.264 ;
     RECT  20.507 2.736 21.407 3.6 ;
     RECT  21.407 3.186 21.415 3.6 ;
     RECT  20.507 5.166 21.415 6.3 ;
     RECT  20.615 15.534 21.415 15.984 ;
     RECT  21.415 3.186 21.479 4.104 ;
     RECT  20.543 10.296 21.479 10.764 ;
     RECT  20.543 11.916 21.479 12.114 ;
     RECT  20.615 20.052 21.479 20.484 ;
     RECT  20.579 23.094 21.479 23.346 ;
     RECT  21.479 3.186 21.515 3.204 ;
     RECT  21.479 4.086 21.515 4.104 ;
     RECT  21.415 5.166 21.515 6.606 ;
     RECT  20.507 7.398 21.515 8.694 ;
     RECT  21.479 10.296 21.515 10.314 ;
     RECT  21.479 11.916 21.515 11.934 ;
     RECT  21.415 15.534 21.515 16.092 ;
     RECT  20.507 18.396 21.515 18.414 ;
     RECT  21.479 20.466 21.515 20.484 ;
     RECT  20.615 21.24 21.515 21.258 ;
     RECT  21.479 23.328 21.515 23.346 ;
     RECT  20.507 25.146 21.515 26.739 ;
     RECT  21.515 26.721 21.587 26.739 ;
     RECT  21.487 27.954 21.587 27.972 ;
    LAYER M3 ;
     RECT  21.492 0.715 21.51 0.811 ;
     RECT  19.404 1.003 19.422 1.099 ;
     RECT  21.456 0.811 21.51 1.195 ;
     RECT  1.764 1.099 1.782 1.291 ;
     RECT  20.196 0.907 20.214 1.291 ;
     RECT  3.6 1.195 3.618 1.387 ;
     RECT  18.756 1.099 19.422 1.387 ;
     RECT  3.42 1.387 3.618 1.483 ;
     RECT  18.18 1.387 19.422 1.579 ;
     RECT  2.556 1.579 2.574 1.771 ;
     RECT  3.42 1.483 3.654 1.771 ;
     RECT  18.18 1.579 19.458 1.771 ;
     RECT  20.196 1.291 20.286 1.771 ;
     RECT  16.164 1.759 16.182 1.831 ;
     RECT  18.18 1.771 20.286 1.831 ;
     RECT  2.556 1.771 3.654 1.876 ;
     RECT  4.464 1.831 4.482 1.876 ;
     RECT  16.164 1.831 16.866 1.876 ;
     RECT  17.856 1.831 20.286 1.876 ;
     RECT  6.624 1.876 6.642 1.921 ;
     RECT  6.552 1.921 6.642 1.957 ;
     RECT  15.084 1.921 15.102 1.957 ;
     RECT  15.084 1.957 15.138 1.993 ;
     RECT  16.164 1.876 20.286 1.993 ;
     RECT  6.12 1.957 6.642 2.029 ;
     RECT  14.22 1.876 14.238 2.029 ;
     RECT  1.548 1.291 1.782 2.059 ;
     RECT  2.556 1.876 4.482 2.059 ;
     RECT  15.084 1.993 20.286 2.059 ;
     RECT  1.548 2.059 4.482 2.101 ;
     RECT  5.436 2.029 6.642 2.101 ;
     RECT  13.215 2.143 13.305 2.191 ;
     RECT  14.22 2.029 14.31 2.191 ;
     RECT  15.084 2.059 20.502 2.191 ;
     RECT  7.815 2.143 7.905 2.251 ;
     RECT  21.42 1.195 21.51 2.251 ;
     RECT  1.548 2.101 6.642 2.299 ;
     RECT  7.815 2.251 7.938 2.299 ;
     RECT  11.988 2.263 12.006 2.299 ;
     RECT  11.88 2.299 12.006 2.335 ;
     RECT  11.88 2.335 12.294 2.371 ;
     RECT  1.548 2.299 7.938 2.413 ;
     RECT  11.88 2.371 12.402 2.461 ;
     RECT  13.215 2.191 20.502 2.461 ;
     RECT  9.216 2.461 9.234 2.497 ;
     RECT  10.872 2.227 10.89 2.497 ;
     RECT  11.88 2.461 20.502 2.497 ;
     RECT  9.216 2.497 9.306 2.533 ;
     RECT  9.18 2.533 9.306 2.731 ;
     RECT  21.384 2.251 21.51 2.731 ;
     RECT  1.548 2.413 8.097 2.839 ;
     RECT  21.312 2.731 21.51 2.861 ;
     RECT  1.548 2.839 8.262 2.875 ;
     RECT  9.144 2.731 9.306 2.875 ;
     RECT  10.116 2.497 20.502 3.101 ;
     RECT  1.548 2.875 9.306 3.137 ;
     RECT  10.116 3.101 19.458 3.137 ;
     RECT  1.728 3.137 9.306 3.145 ;
     RECT  10.116 3.137 19.422 3.145 ;
     RECT  21.384 2.861 21.51 3.209 ;
     RECT  1.728 3.145 19.422 3.299 ;
     RECT  1.728 3.299 8.406 3.443 ;
     RECT  0.324 2.731 0.342 3.451 ;
     RECT  1.728 3.443 8.262 3.479 ;
     RECT  21.384 3.209 21.474 3.605 ;
     RECT  0.144 3.451 0.342 3.629 ;
     RECT  21.42 3.605 21.474 4.072 ;
     RECT  21.42 4.072 21.51 4.109 ;
     RECT  21.42 4.109 21.438 4.157 ;
     RECT  1.728 3.479 8.19 4.261 ;
     RECT  9.144 3.299 19.422 4.261 ;
     RECT  1.728 4.261 19.422 4.267 ;
     RECT  20.196 3.101 20.502 4.267 ;
     RECT  0.324 4.363 0.342 4.493 ;
     RECT  21.492 5.035 21.51 5.131 ;
     RECT  21.312 5.131 21.51 5.261 ;
     RECT  0.828 5.035 0.846 5.323 ;
     RECT  0.108 5.323 0.846 5.419 ;
     RECT  1.728 4.267 20.502 5.419 ;
     RECT  21.456 5.261 21.51 6.583 ;
     RECT  21.42 6.583 21.51 6.653 ;
     RECT  0.108 5.419 20.502 6.989 ;
     RECT  19.908 6.989 20.502 7.259 ;
     RECT  21.492 6.653 21.51 7.42 ;
     RECT  21.456 7.42 21.51 7.819 ;
     RECT  21.42 7.819 21.51 8.033 ;
     RECT  20.196 7.259 20.502 8.239 ;
     RECT  21.456 8.033 21.51 8.429 ;
     RECT  0.108 6.989 19.026 8.437 ;
     RECT  0.108 8.437 19.098 8.473 ;
     RECT  19.944 8.239 20.502 8.525 ;
     RECT  0.108 8.473 19.17 8.609 ;
     RECT  19.98 8.525 20.502 8.621 ;
     RECT  21.492 8.429 21.51 8.699 ;
     RECT  0.108 8.609 19.098 8.735 ;
     RECT  0.108 8.735 0.234 8.909 ;
     RECT  1.404 8.735 19.098 9.391 ;
     RECT  1.404 9.391 19.422 9.485 ;
     RECT  20.232 8.621 20.502 9.779 ;
     RECT  20.232 9.779 20.466 9.931 ;
     RECT  0.108 8.909 0.126 10.027 ;
     RECT  1.404 9.485 19.098 10.085 ;
     RECT  21.312 10.027 21.33 10.123 ;
     RECT  0.108 10.027 0.342 10.157 ;
     RECT  21.312 10.123 21.51 10.319 ;
     RECT  19.908 9.931 20.466 10.561 ;
     RECT  21.312 10.319 21.474 10.637 ;
     RECT  1.404 10.085 19.026 11.101 ;
     RECT  19.908 10.561 20.502 11.101 ;
     RECT  21.42 10.637 21.474 11.117 ;
     RECT  0.108 10.157 0.198 11.209 ;
     RECT  1.404 11.101 19.17 11.237 ;
     RECT  21.456 11.117 21.474 11.371 ;
     RECT  19.908 11.101 20.538 11.501 ;
     RECT  0.108 11.209 0.558 11.693 ;
     RECT  19.908 11.501 20.502 11.803 ;
     RECT  19.872 11.803 20.502 11.894 ;
     RECT  21.456 11.371 21.51 11.939 ;
     RECT  0.108 11.693 0.342 12.047 ;
     RECT  0.108 12.047 0.162 12.077 ;
     RECT  1.404 11.237 19.098 12.091 ;
     RECT  21.456 11.939 21.474 12.119 ;
     RECT  1.404 12.091 19.134 12.209 ;
     RECT  19.98 11.894 20.502 12.289 ;
     RECT  19.98 12.289 20.538 12.461 ;
     RECT  0.144 12.077 0.162 12.509 ;
     RECT  1.404 12.209 18.99 12.785 ;
     RECT  19.98 12.461 20.502 12.865 ;
     RECT  1.44 12.785 18.99 13.063 ;
     RECT  1.44 13.063 19.17 13.195 ;
     RECT  19.944 12.865 20.502 13.195 ;
     RECT  1.44 13.195 20.502 13.667 ;
     RECT  0.108 13.291 0.126 13.675 ;
     RECT  21.492 13.483 21.51 13.915 ;
     RECT  0.108 13.675 0.162 13.945 ;
     RECT  1.44 13.667 20.466 14.059 ;
     RECT  21.42 13.915 21.51 14.093 ;
     RECT  0.108 13.945 0.198 14.143 ;
     RECT  0.036 14.143 0.198 14.347 ;
     RECT  1.404 14.059 20.466 14.44 ;
     RECT  0.036 14.347 0.342 14.477 ;
     RECT  1.404 14.44 20.502 14.647 ;
     RECT  1.404 14.647 20.538 14.957 ;
     RECT  1.404 14.957 20.502 15.245 ;
     RECT  19.908 15.245 20.502 15.287 ;
     RECT  0.036 14.477 0.198 15.457 ;
     RECT  0.036 15.457 0.234 15.601 ;
     RECT  0.036 15.601 0.522 15.763 ;
     RECT  21.492 14.093 21.51 16.027 ;
     RECT  1.404 15.245 19.098 16.069 ;
     RECT  19.944 15.287 20.502 16.069 ;
     RECT  21.42 16.027 21.51 16.097 ;
     RECT  0.036 15.763 0.558 16.105 ;
     RECT  1.404 16.069 20.502 16.105 ;
     RECT  21.492 16.097 21.51 16.109 ;
     RECT  0.036 16.105 20.538 16.141 ;
     RECT  0.036 16.141 20.61 16.331 ;
     RECT  0.108 16.331 20.61 16.493 ;
     RECT  1.152 16.493 20.61 16.877 ;
     RECT  1.152 16.877 20.538 17.069 ;
     RECT  1.152 17.069 20.502 17.249 ;
     RECT  0.108 16.493 0.234 17.491 ;
     RECT  1.152 17.249 1.17 17.491 ;
     RECT  2.088 17.249 20.502 17.681 ;
     RECT  0.108 17.491 1.17 17.837 ;
     RECT  21.492 17.995 21.51 18.419 ;
     RECT  2.088 17.681 19.422 18.499 ;
     RECT  0.108 17.837 0.162 18.509 ;
     RECT  1.152 17.837 1.17 18.571 ;
     RECT  0.468 18.571 1.17 18.769 ;
     RECT  2.088 18.499 19.458 18.769 ;
     RECT  20.232 17.681 20.502 18.769 ;
     RECT  0.468 18.769 20.502 18.989 ;
     RECT  20.376 18.989 20.502 19.051 ;
     RECT  0.468 18.989 19.422 19.067 ;
     RECT  0.468 19.067 19.314 19.345 ;
     RECT  20.376 19.051 20.538 20.011 ;
     RECT  0.108 19.345 19.314 20.119 ;
     RECT  20.232 20.011 20.538 20.119 ;
     RECT  0.108 20.119 20.538 20.236 ;
     RECT  21.456 20.047 21.474 20.299 ;
     RECT  0.108 20.236 20.574 20.551 ;
     RECT  0.108 20.551 20.61 20.717 ;
     RECT  1.152 20.717 20.61 20.813 ;
     RECT  21.456 20.299 21.51 21.263 ;
     RECT  21.456 21.263 21.474 21.389 ;
     RECT  1.152 20.813 1.17 21.497 ;
     RECT  0.108 20.717 0.234 21.505 ;
     RECT  0.108 21.505 0.558 21.677 ;
     RECT  2.196 20.813 20.61 22.109 ;
     RECT  0.108 21.677 0.234 22.621 ;
     RECT  0.108 22.621 0.558 22.925 ;
     RECT  2.232 22.109 20.61 23.089 ;
     RECT  1.692 23.089 20.61 23.309 ;
     RECT  21.456 23.089 21.474 23.323 ;
     RECT  0.108 22.925 0.522 23.501 ;
     RECT  0.144 23.501 0.522 23.692 ;
     RECT  1.692 23.309 20.574 23.693 ;
     RECT  0.144 23.692 0.558 24.205 ;
     RECT  1.692 23.693 19.134 24.205 ;
     RECT  19.944 23.693 20.574 24.241 ;
     RECT  0.144 24.205 19.134 24.367 ;
     RECT  0.108 24.367 19.134 24.475 ;
     RECT  0.108 24.475 19.206 24.601 ;
     RECT  19.944 24.241 20.61 24.601 ;
     RECT  0.108 24.601 20.61 24.653 ;
     RECT  1.152 24.653 20.61 25.325 ;
     RECT  0.108 24.653 0.162 25.435 ;
     RECT  0.108 25.435 0.234 25.483 ;
     RECT  21.456 23.323 21.51 25.483 ;
     RECT  0.108 25.483 0.27 25.675 ;
     RECT  21.348 25.483 21.51 25.805 ;
     RECT  0.108 25.675 0.342 25.825 ;
     RECT  1.152 25.325 20.574 25.825 ;
     RECT  0.108 25.825 20.574 26.189 ;
     RECT  21.492 25.805 21.51 26.393 ;
     RECT  0.144 26.189 20.574 26.401 ;
     RECT  0.144 26.401 20.646 26.573 ;
     RECT  0.144 26.573 0.162 27.149 ;
     RECT  1.152 26.573 20.646 27.245 ;
     RECT  1.152 27.245 19.458 27.301 ;
     RECT  0.18 27.301 19.458 27.329 ;
     RECT  0.18 27.329 10.314 27.365 ;
     RECT  0.18 27.365 9.126 27.401 ;
     RECT  5.652 27.401 9.126 27.509 ;
     RECT  11.088 27.329 19.458 27.671 ;
     RECT  5.652 27.509 8.838 27.707 ;
     RECT  11.664 27.671 19.458 27.707 ;
     RECT  20.484 27.245 20.646 27.725 ;
     RECT  5.652 27.707 8.73 27.743 ;
     RECT  11.844 27.707 19.458 27.743 ;
     RECT  12.492 27.743 19.458 27.773 ;
     RECT  20.484 27.725 20.538 27.821 ;
     RECT  5.652 27.743 8.097 27.827 ;
     RECT  0.18 27.401 4.626 27.869 ;
     RECT  5.652 27.827 7.905 27.869 ;
     RECT  10.188 27.365 10.314 27.869 ;
     RECT  12.492 27.773 17.082 27.869 ;
     RECT  17.82 27.773 19.458 27.869 ;
     RECT  0.54 27.869 4.626 27.905 ;
     RECT  6.264 27.869 7.905 27.905 ;
     RECT  10.296 27.869 10.314 27.905 ;
     RECT  12.492 27.869 14.49 27.905 ;
     RECT  0.54 27.905 4.122 27.917 ;
     RECT  1.656 27.917 3.474 27.941 ;
     RECT  6.876 27.905 7.905 27.941 ;
     RECT  12.636 27.905 13.305 27.941 ;
     RECT  14.148 27.905 14.166 27.941 ;
     RECT  15.228 27.869 15.246 27.941 ;
     RECT  21.564 26.716 21.582 27.949 ;
     RECT  18.288 27.869 19.458 27.977 ;
     RECT  21.492 27.949 21.582 27.977 ;
     RECT  1.656 27.941 3.402 28.013 ;
     RECT  21.492 27.977 21.51 28.013 ;
     RECT  7.815 27.941 7.905 28.097 ;
     RECT  13.215 27.941 13.305 28.097 ;
     RECT  18.615 27.977 19.458 28.097 ;
     RECT  19.26 28.097 19.458 28.109 ;
     RECT  16.092 27.869 16.83 28.205 ;
     RECT  0.54 27.917 0.558 28.301 ;
     RECT  19.404 28.109 19.458 28.301 ;
     RECT  16.812 28.205 16.83 28.397 ;
     RECT  6.948 27.941 6.966 28.493 ;
     RECT  20.52 27.821 20.538 28.493 ;
     RECT  1.692 28.013 2.826 28.589 ;
     RECT  19.44 28.301 19.458 28.589 ;
     RECT  2.808 28.589 2.826 29.069 ;
     RECT  1.692 28.589 1.71 29.453 ;
    LAYER M4 ;
     RECT  0.06 1.104 1.721 29.448 ;
     RECT  1.721 1.104 1.793 29.064 ;
     RECT  1.793 1.2 2.585 29.064 ;
     RECT  2.585 29.04 2.837 29.064 ;
     RECT  2.585 1.2 3.125 28.008 ;
     RECT  3.125 2.496 3.413 28.008 ;
     RECT  3.413 2.496 3.485 27.912 ;
     RECT  3.125 1.2 3.629 1.512 ;
     RECT  3.629 1.488 3.665 1.512 ;
     RECT  3.485 2.496 3.809 21.48 ;
     RECT  3.809 4.512 4.133 21.48 ;
     RECT  3.485 22.56 4.133 27.912 ;
     RECT  4.133 9.072 4.453 21.48 ;
     RECT  4.133 22.56 4.453 27.384 ;
     RECT  4.133 4.512 5.065 7.992 ;
     RECT  3.809 2.496 5.533 2.856 ;
     RECT  4.453 9.072 5.573 27.384 ;
     RECT  5.573 19.344 6.253 27.384 ;
     RECT  5.573 9.072 6.541 18.12 ;
     RECT  5.065 3.888 6.757 7.992 ;
     RECT  6.541 9.072 6.757 18.264 ;
     RECT  6.757 3.888 6.833 18.264 ;
     RECT  6.253 19.344 6.851 27.864 ;
     RECT  6.851 19.344 6.937 27.912 ;
     RECT  6.937 19.344 7.021 28.488 ;
     RECT  7.021 19.344 7.045 28.092 ;
     RECT  5.533 2.256 7.141 2.856 ;
     RECT  6.833 3.888 7.141 9.624 ;
     RECT  6.833 10.896 7.585 18.264 ;
     RECT  7.045 19.248 7.585 28.092 ;
     RECT  7.141 2.256 7.808 9.624 ;
     RECT  7.585 10.896 7.808 28.092 ;
     RECT  7.808 2.148 7.912 28.092 ;
     RECT  7.912 2.256 7.949 27.822 ;
     RECT  7.949 2.418 8.104 27.822 ;
     RECT  8.104 22.8 8.345 27.384 ;
     RECT  8.345 26.784 8.705 27.384 ;
     RECT  8.345 22.8 8.957 25.8 ;
     RECT  8.104 2.496 9.133 2.76 ;
     RECT  8.104 8.784 9.133 21.672 ;
     RECT  8.957 22.8 9.133 24.504 ;
     RECT  9.133 2.496 9.277 2.856 ;
     RECT  8.104 4.368 9.421 7.704 ;
     RECT  9.133 8.784 9.421 24.504 ;
     RECT  9.421 4.368 9.461 24.504 ;
     RECT  8.957 25.536 9.529 25.8 ;
     RECT  8.705 26.784 9.529 27.192 ;
     RECT  9.461 9.696 10.037 24.504 ;
     RECT  10.037 11.52 10.069 24.504 ;
     RECT  9.529 25.536 10.069 27.192 ;
     RECT  10.069 11.52 10.105 27.192 ;
     RECT  9.277 2.496 10.748 3.384 ;
     RECT  9.461 4.368 10.748 8.568 ;
     RECT  10.748 2.496 10.835 8.568 ;
     RECT  10.835 2.496 10.865 3.384 ;
     RECT  10.105 11.52 11.136 27.336 ;
     RECT  10.037 9.696 11.329 10.488 ;
     RECT  11.136 11.52 11.329 27.24 ;
     RECT  11.329 9.696 11.333 27.24 ;
     RECT  10.835 4.368 11.365 8.568 ;
     RECT  11.333 9.696 11.365 26.808 ;
     RECT  11.365 4.368 11.549 26.808 ;
     RECT  11.549 4.368 11.797 8.28 ;
     RECT  10.865 2.496 11.833 2.856 ;
     RECT  11.797 3.888 11.833 8.28 ;
     RECT  11.549 9.264 12.205 26.808 ;
     RECT  11.833 2.496 12.661 8.28 ;
     RECT  12.205 9.264 12.661 26.664 ;
     RECT  12.661 2.496 13.208 26.664 ;
     RECT  13.208 2.148 13.312 28.092 ;
     RECT  13.312 2.418 13.504 27.822 ;
     RECT  13.504 2.688 13.853 27.528 ;
     RECT  13.853 2.688 14.429 7.944 ;
     RECT  13.853 8.976 14.897 27.528 ;
     RECT  14.897 8.976 14.933 27.144 ;
     RECT  14.933 12.768 14.969 27.144 ;
     RECT  14.969 16.128 15.005 27.144 ;
     RECT  14.429 3.264 15.325 7.944 ;
     RECT  14.933 8.976 15.325 11.688 ;
     RECT  15.005 16.128 15.365 17.784 ;
     RECT  15.005 18.96 15.365 27.144 ;
     RECT  15.365 19.872 15.509 20.28 ;
     RECT  15.509 20.16 15.581 20.184 ;
     RECT  15.325 3.264 15.613 11.688 ;
     RECT  15.613 3.12 15.649 11.688 ;
     RECT  15.365 16.128 15.797 17.736 ;
     RECT  15.649 2.736 15.901 11.688 ;
     RECT  14.969 12.768 15.901 15.048 ;
     RECT  15.365 21.36 16.045 27.144 ;
     RECT  16.045 21.36 16.081 27.336 ;
     RECT  15.901 2.736 16.261 15.048 ;
     RECT  15.797 16.128 16.261 17.112 ;
     RECT  16.081 21.36 16.369 28.2 ;
     RECT  16.261 2.736 16.513 17.112 ;
     RECT  16.477 18.144 16.657 18.168 ;
     RECT  16.513 2.448 16.801 17.112 ;
     RECT  16.657 18.144 16.801 19.032 ;
     RECT  16.369 21.168 16.801 28.2 ;
     RECT  16.801 2.448 16.981 19.032 ;
     RECT  16.981 2.448 17.269 19.224 ;
     RECT  16.801 20.4 17.269 28.392 ;
     RECT  17.269 2.448 17.345 28.392 ;
     RECT  18.169 1.392 18.241 1.416 ;
     RECT  17.345 2.448 18.241 17.112 ;
     RECT  18.241 1.392 18.608 17.112 ;
     RECT  17.345 18.144 18.608 28.392 ;
     RECT  18.608 1.392 18.745 28.392 ;
     RECT  18.745 1.104 18.904 28.392 ;
     RECT  18.904 20.4 18.929 28.392 ;
     RECT  18.904 9.456 19.037 19.32 ;
     RECT  18.904 1.104 19.393 8.472 ;
     RECT  18.929 22.224 19.429 28.392 ;
     RECT  19.393 1.008 19.933 8.472 ;
     RECT  19.037 9.456 19.933 18.984 ;
     RECT  18.929 20.4 19.933 21.096 ;
     RECT  19.429 22.224 19.933 28.584 ;
     RECT  19.933 1.008 20.185 18.984 ;
     RECT  19.933 20.4 20.221 28.584 ;
     RECT  20.185 0.912 20.473 18.984 ;
     RECT  20.221 20.016 20.473 28.584 ;
     RECT  20.473 0.912 21.445 28.584 ;
     RECT  21.445 0.816 21.481 28.584 ;
     RECT  21.481 0.72 21.564 28.584 ;
    LAYER M5 ;
     RECT  2.4 2.137 2.52 2.151 ;
     RECT  7.8 2.137 7.92 2.151 ;
     RECT  13.2 2.137 13.32 2.151 ;
     RECT  18.6 2.137 18.72 2.151 ;
     RECT  13.2 2.151 13.512 2.581 ;
     RECT  21.408 2.581 21.432 2.867 ;
     RECT  0.144 2.677 0.168 3.397 ;
     RECT  7.8 2.151 8.112 3.685 ;
     RECT  2.4 2.151 2.712 3.877 ;
     RECT  0.144 3.397 0.264 4.067 ;
     RECT  7.152 3.685 8.112 4.357 ;
     RECT  6.24 4.357 8.112 4.595 ;
     RECT  17.04 4.405 17.064 4.643 ;
     RECT  2.4 3.877 2.856 4.739 ;
     RECT  9.12 4.741 9.144 4.981 ;
     RECT  10.8 3.925 10.824 5.461 ;
     RECT  13.056 2.581 13.512 5.795 ;
     RECT  6.24 4.595 6.264 5.893 ;
     RECT  2.4 4.739 2.808 6.229 ;
     RECT  10.8 5.461 11.112 6.229 ;
     RECT  13.104 5.795 13.512 6.275 ;
     RECT  9.12 4.981 9.528 6.323 ;
     RECT  0.144 4.067 0.168 6.901 ;
     RECT  0.144 6.901 0.264 6.947 ;
     RECT  10.8 6.229 11.784 7.907 ;
     RECT  9.504 6.323 9.528 7.909 ;
     RECT  10.8 7.907 11.112 7.909 ;
     RECT  9.504 7.909 11.112 8.531 ;
     RECT  0.24 6.947 0.264 8.821 ;
     RECT  2.4 6.229 3.288 9.013 ;
     RECT  5.808 5.893 6.264 9.061 ;
     RECT  13.2 6.275 13.512 9.541 ;
     RECT  0.192 8.821 0.264 9.877 ;
     RECT  7.8 4.595 8.112 10.213 ;
     RECT  9.504 8.531 9.528 10.213 ;
     RECT  2.304 9.013 3.288 10.357 ;
     RECT  10.8 8.531 11.112 10.453 ;
     RECT  10.8 10.453 11.64 10.499 ;
     RECT  2.304 10.357 3.912 10.595 ;
     RECT  21.408 10.453 21.432 10.643 ;
     RECT  5.808 9.061 6.552 11.173 ;
     RECT  0.144 9.877 0.264 11.365 ;
     RECT  0.144 11.365 0.552 11.507 ;
     RECT  2.304 10.595 3.288 11.749 ;
     RECT  2.304 11.749 3.384 11.845 ;
     RECT  5.616 11.173 6.552 11.987 ;
     RECT  2.304 11.845 3.912 12.035 ;
     RECT  13.2 9.541 13.656 12.085 ;
     RECT  2.4 12.035 3.912 12.517 ;
     RECT  0.144 11.507 0.264 12.613 ;
     RECT  2.4 12.517 4.632 12.803 ;
     RECT  0.144 12.613 0.312 12.805 ;
     RECT  13.2 12.085 13.704 13.189 ;
     RECT  13.008 13.189 13.704 13.475 ;
     RECT  5.808 11.987 6.552 13.715 ;
     RECT  13.2 13.475 13.704 13.715 ;
     RECT  0.144 12.805 0.36 13.765 ;
     RECT  6 13.715 6.552 14.101 ;
     RECT  7.8 10.213 9.528 14.101 ;
     RECT  0.144 13.765 0.408 14.291 ;
     RECT  2.4 12.803 3.432 14.291 ;
     RECT  11.088 10.499 11.64 14.291 ;
     RECT  2.4 14.291 3.384 14.387 ;
     RECT  13.2 13.715 13.512 14.917 ;
     RECT  6 14.101 9.528 15.061 ;
     RECT  13.2 14.917 14.424 15.347 ;
     RECT  13.2 15.347 13.512 15.541 ;
     RECT  13.008 15.541 13.512 15.683 ;
     RECT  0.144 14.291 0.36 15.827 ;
     RECT  6 15.061 10.104 16.019 ;
     RECT  0.336 15.827 0.36 16.067 ;
     RECT  4.608 12.803 4.632 16.885 ;
     RECT  11.088 14.291 11.112 17.077 ;
     RECT  4.512 16.885 4.632 17.221 ;
     RECT  6 16.019 9.528 17.221 ;
     RECT  10.752 17.077 11.208 17.459 ;
     RECT  2.4 14.387 3.288 17.461 ;
     RECT  13.2 15.683 13.512 17.605 ;
     RECT  4.512 17.221 9.528 17.653 ;
     RECT  4.368 17.653 9.528 17.987 ;
     RECT  2.4 17.461 3.336 18.133 ;
     RECT  4.608 17.987 9.528 18.181 ;
     RECT  10.752 17.459 11.112 18.181 ;
     RECT  12.384 17.605 13.512 18.421 ;
     RECT  12.384 18.421 13.608 18.563 ;
     RECT  0.336 17.893 0.36 18.565 ;
     RECT  13.2 18.563 13.608 18.613 ;
     RECT  2.4 18.133 3.624 18.709 ;
     RECT  0.144 18.565 0.36 18.851 ;
     RECT  2.304 18.709 3.624 18.899 ;
     RECT  14.784 18.805 14.808 18.995 ;
     RECT  2.304 18.899 3.432 19.427 ;
     RECT  2.304 19.427 3.336 19.715 ;
     RECT  0.24 18.851 0.36 19.765 ;
     RECT  0.24 19.765 0.408 19.813 ;
     RECT  4.608 18.181 11.112 20.003 ;
     RECT  4.608 20.003 4.632 20.099 ;
     RECT  13.2 18.613 13.656 20.195 ;
     RECT  6 20.003 11.112 20.291 ;
     RECT  9.264 20.291 11.112 20.293 ;
     RECT  12.144 19.909 12.168 20.293 ;
     RECT  9.264 20.293 12.168 20.435 ;
     RECT  0.192 19.813 0.504 20.675 ;
     RECT  9.264 20.435 11.112 20.723 ;
     RECT  0.384 20.675 0.504 21.011 ;
     RECT  9.264 20.723 9.288 21.155 ;
     RECT  2.4 19.715 3.336 21.445 ;
     RECT  0.384 21.011 0.408 21.731 ;
     RECT  11.088 20.723 11.112 21.731 ;
     RECT  12.144 20.435 12.168 21.733 ;
     RECT  13.2 20.195 13.512 21.733 ;
     RECT  12.144 21.733 13.512 22.259 ;
     RECT  0.192 21.973 0.36 22.355 ;
     RECT  0.192 22.355 0.216 22.741 ;
     RECT  6 20.291 8.112 23.651 ;
     RECT  0.144 22.741 0.216 23.701 ;
     RECT  0.144 23.701 0.36 23.891 ;
     RECT  6.24 23.651 8.112 25.715 ;
     RECT  0.144 23.891 0.264 25.717 ;
     RECT  2.4 21.445 4.056 25.813 ;
     RECT  6.864 25.715 8.112 25.813 ;
     RECT  2.304 25.813 4.056 25.907 ;
     RECT  2.304 25.907 3.768 26.101 ;
     RECT  2.256 26.101 3.768 26.291 ;
     RECT  5.088 25.189 5.112 26.675 ;
     RECT  2.256 26.291 2.856 26.819 ;
     RECT  6.864 25.813 8.232 26.819 ;
     RECT  12.144 22.259 12.168 26.819 ;
     RECT  2.256 26.819 2.712 27.251 ;
     RECT  11.04 24.661 11.064 27.347 ;
     RECT  0.144 25.717 0.456 27.637 ;
     RECT  0.144 27.637 0.504 27.733 ;
     RECT  2.4 27.251 2.712 28.089 ;
     RECT  6.864 26.819 8.112 28.089 ;
     RECT  13.2 22.259 13.512 28.089 ;
     RECT  18.6 2.151 18.912 28.089 ;
     RECT  2.4 28.089 2.52 28.103 ;
     RECT  6.864 28.089 7.92 28.103 ;
     RECT  13.2 28.089 13.32 28.103 ;
     RECT  18.6 28.089 18.72 28.103 ;
     RECT  0.144 27.733 0.6 29.171 ;
     RECT  0.144 29.171 0.504 29.267 ;
     RECT  0.144 29.267 0.168 29.363 ;
     RECT  6.864 28.103 6.984 30.224 ;
  END
END dsfd_rly_283_WE
END LIBRARY
